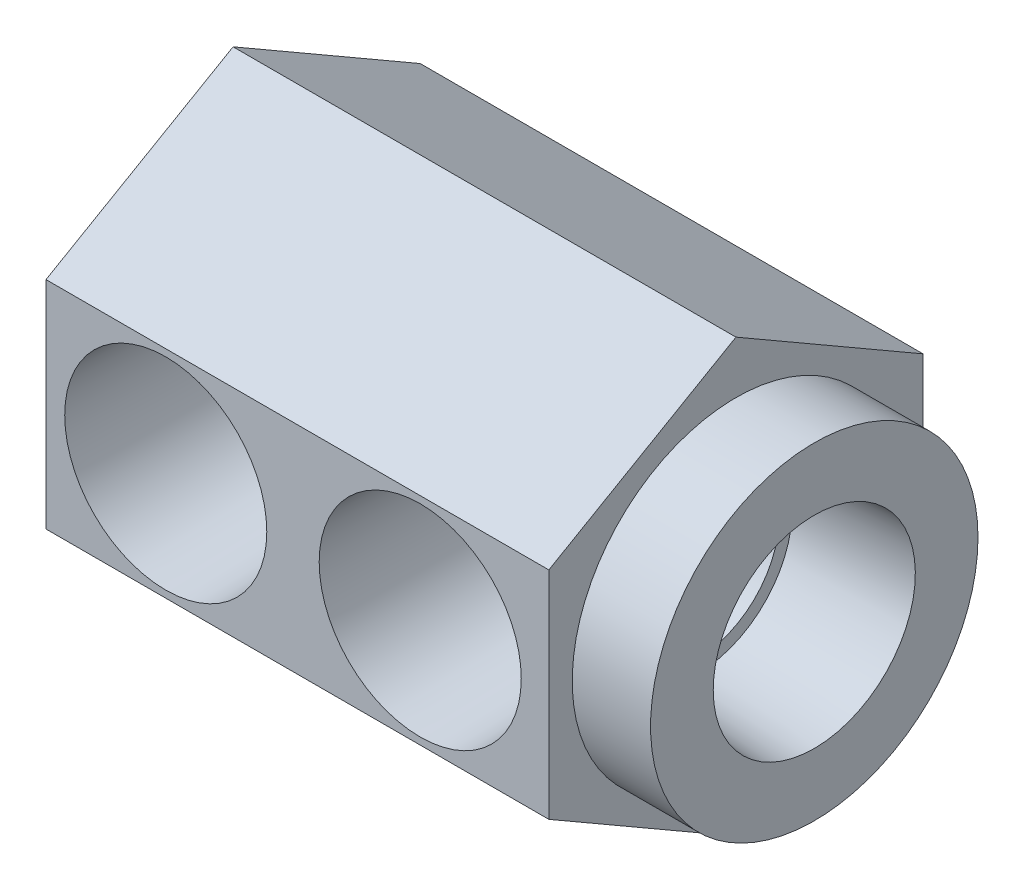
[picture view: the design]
ISO-10303-21;
HEADER;
FILE_DESCRIPTION(('STEP AP214'),'2;1');
FILE_NAME('part.step','',(''),(''),'','','');
FILE_SCHEMA(('AUTOMOTIVE_DESIGN { 1 0 10303 214 1 1 1 1 }'));
ENDSEC;
DATA;
#1=APPLICATION_CONTEXT('core data for automotive mechanical design processes');
#2=APPLICATION_PROTOCOL_DEFINITION('international standard','automotive_design',2000,#1);
#3=PRODUCT_CONTEXT('',#1,'mechanical');
#4=PRODUCT('Part','Part','',(#3));
#5=PRODUCT_RELATED_PRODUCT_CATEGORY('part','',(#4));
#6=PRODUCT_DEFINITION_FORMATION('','',#4);
#7=PRODUCT_DEFINITION_CONTEXT('part definition',#1,'design');
#8=PRODUCT_DEFINITION('design','',#6,#7);
#9=PRODUCT_DEFINITION_SHAPE('','',#8);
#10=(LENGTH_UNIT() NAMED_UNIT(*) SI_UNIT(.MILLI.,.METRE.));
#11=(NAMED_UNIT(*) PLANE_ANGLE_UNIT() SI_UNIT($,.RADIAN.));
#12=(NAMED_UNIT(*) SI_UNIT($,.STERADIAN.) SOLID_ANGLE_UNIT());
#13=UNCERTAINTY_MEASURE_WITH_UNIT(LENGTH_MEASURE(1.E-05),#10,'distance_accuracy_value','');
#14=(GEOMETRIC_REPRESENTATION_CONTEXT(3) GLOBAL_UNCERTAINTY_ASSIGNED_CONTEXT((#13)) GLOBAL_UNIT_ASSIGNED_CONTEXT((#10,
#11,#12)) REPRESENTATION_CONTEXT('',''));
#15=CARTESIAN_POINT('',(0.,0.,0.));
#16=DIRECTION('',(0.,0.,1.));
#17=DIRECTION('',(1.,0.,0.));
#18=AXIS2_PLACEMENT_3D('',#15,#16,#17);
#19=CARTESIAN_POINT('',(30.9626,0.,2.6797));
#20=DIRECTION('',(0.,0.,-1.));
#21=DIRECTION('',(-1.,0.,0.));
#22=AXIS2_PLACEMENT_3D('',#19,#20,#21);
#23=PLANE('',#22);
#24=CARTESIAN_POINT('',(25.4,0.,2.6797));
#25=DIRECTION('',(0.,0.,1.));
#26=DIRECTION('',(1.,0.,0.));
#27=AXIS2_PLACEMENT_3D('',#24,#25,#26);
#28=CIRCLE('',#27,6.55797879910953);
#29=CARTESIAN_POINT('',(29.7949930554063,4.86735266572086,2.6797));
#30=VERTEX_POINT('',#29);
#31=CARTESIAN_POINT('',(19.531703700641,2.92748774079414,2.6797));
#32=VERTEX_POINT('',#31);
#33=EDGE_CURVE('E312',#30,#32,#28,.T.);
#34=ORIENTED_EDGE('',*,*,#33,.T.);
#35=DIRECTION('',(1.,0.,0.));
#36=VECTOR('',#35,1.);
#37=CARTESIAN_POINT('',(39.44747,2.92748774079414,2.6797));
#38=LINE('',#37,#36);
#39=CARTESIAN_POINT('',(20.6700598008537,2.92748774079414,2.6797));
#40=VERTEX_POINT('',#39);
#41=EDGE_CURVE('E677',#32,#40,#38,.T.);
#42=ORIENTED_EDGE('',*,*,#41,.T.);
#43=CARTESIAN_POINT('',(25.4,0.,2.6797));
#44=DIRECTION('',(0.,0.,1.));
#45=DIRECTION('',(1.,0.,0.));
#46=AXIS2_PLACEMENT_3D('',#43,#44,#45);
#47=CIRCLE('',#46,5.56260000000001);
#48=CARTESIAN_POINT('',(28.0928417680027,4.86735266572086,2.6797));
#49=VERTEX_POINT('',#48);
#50=EDGE_CURVE('E311',#49,#40,#47,.T.);
#51=ORIENTED_EDGE('',*,*,#50,.F.);
#52=DIRECTION('',(-1.,0.,0.));
#53=VECTOR('',#52,1.);
#54=CARTESIAN_POINT('',(-12.2161702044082,4.86735266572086,2.6797));
#55=LINE('',#54,#53);
#56=EDGE_CURVE('E411',#49,#30,#55,.F.);
#57=ORIENTED_EDGE('',*,*,#56,.T.);
#58=EDGE_LOOP('',(#34,#42,#51,#57));
#59=FACE_BOUND('',#58,.T.);
#60=ADVANCED_FACE('F35',(#59),#23,.F.);
#61=CARTESIAN_POINT('',(26.74747,0.,-5.55625));
#62=DIRECTION('',(1.,0.,0.));
#63=DIRECTION('',(0.,0.,-1.));
#64=AXIS2_PLACEMENT_3D('',#61,#62,#63);
#65=PLANE('',#64);
#66=DIRECTION('',(0.,0.,1.));
#67=VECTOR('',#66,1.);
#68=CARTESIAN_POINT('',(26.74747,5.39692906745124,12.7));
#69=LINE('',#68,#67);
#70=CARTESIAN_POINT('',(26.74747,5.39692906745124,-1.32101124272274));
#71=VERTEX_POINT('',#70);
#72=CARTESIAN_POINT('',(26.74747,5.39692906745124,1.32101124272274));
#73=VERTEX_POINT('',#72);
#74=EDGE_CURVE('E324',#71,#73,#69,.T.);
#75=ORIENTED_EDGE('',*,*,#74,.F.);
#76=CARTESIAN_POINT('',(26.74747,0.,0.));
#77=DIRECTION('',(-1.,0.,0.));
#78=DIRECTION('',(0.,0.,1.));
#79=AXIS2_PLACEMENT_3D('',#76,#77,#78);
#80=CIRCLE('',#79,5.55625);
#81=EDGE_CURVE('E438',#73,#71,#80,.T.);
#82=ORIENTED_EDGE('',*,*,#81,.F.);
#83=EDGE_LOOP('',(#75,#82));
#84=FACE_BOUND('',#83,.T.);
#85=ADVANCED_FACE('F281',(#84),#65,.T.);
#86=CARTESIAN_POINT('',(39.44747,0.,0.));
#87=DIRECTION('',(1.,0.,0.));
#88=DIRECTION('',(0.,0.,-1.));
#89=AXIS2_PLACEMENT_3D('',#86,#87,#88);
#90=PLANE('',#89);
#91=CARTESIAN_POINT('',(39.44747,0.,0.));
#92=DIRECTION('',(1.,0.,0.));
#93=DIRECTION('',(0.,0.,-1.));
#94=AXIS2_PLACEMENT_3D('',#91,#92,#93);
#95=CIRCLE('',#94,11.1125);
#96=CARTESIAN_POINT('',(39.44747,0.,-11.1125));
#97=VERTEX_POINT('',#96);
#98=EDGE_CURVE('E442',#97,#97,#95,.T.);
#99=ORIENTED_EDGE('',*,*,#98,.T.);
#100=EDGE_LOOP('',(#99));
#101=FACE_BOUND('',#100,.T.);
#102=CARTESIAN_POINT('',(39.44747,0.,0.));
#103=DIRECTION('',(-1.,0.,0.));
#104=DIRECTION('',(0.,0.,1.));
#105=AXIS2_PLACEMENT_3D('',#102,#103,#104);
#106=CIRCLE('',#105,6.85927);
#107=CARTESIAN_POINT('',(39.44747,0.,6.85927));
#108=VERTEX_POINT('',#107);
#109=EDGE_CURVE('E432',#108,#108,#106,.T.);
#110=ORIENTED_EDGE('',*,*,#109,.T.);
#111=EDGE_LOOP('',(#110));
#112=FACE_BOUND('',#111,.T.);
#113=ADVANCED_FACE('F288',(#101,#112),#90,.T.);
#114=CARTESIAN_POINT('',(34.13125,-7.33234841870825,12.7));
#115=DIRECTION('',(1.,0.,0.));
#116=DIRECTION('',(0.,0.,-1.));
#117=AXIS2_PLACEMENT_3D('',#114,#115,#116);
#118=PLANE('',#117);
#119=DIRECTION('',(0.,-1.,0.));
#120=VECTOR('',#119,1.);
#121=CARTESIAN_POINT('',(34.13125,7.33234841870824,12.7));
#122=LINE('',#121,#120);
#123=CARTESIAN_POINT('',(34.13125,7.33234841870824,12.7));
#124=VERTEX_POINT('',#123);
#125=CARTESIAN_POINT('',(34.13125,-7.33234841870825,12.7));
#126=VERTEX_POINT('',#125);
#127=EDGE_CURVE('E448',#124,#126,#122,.T.);
#128=ORIENTED_EDGE('',*,*,#127,.T.);
#129=DIRECTION('',(0.,-0.5,-0.866025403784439));
#130=VECTOR('',#129,1.);
#131=CARTESIAN_POINT('',(34.13125,-7.33234841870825,12.7));
#132=LINE('',#131,#130);
#133=CARTESIAN_POINT('',(34.13125,-14.6646968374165,0.));
#134=VERTEX_POINT('',#133);
#135=EDGE_CURVE('E451',#126,#134,#132,.T.);
#136=ORIENTED_EDGE('',*,*,#135,.T.);
#137=DIRECTION('',(0.,0.500000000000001,-0.866025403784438));
#138=VECTOR('',#137,1.);
#139=CARTESIAN_POINT('',(34.13125,-14.6646968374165,0.));
#140=LINE('',#139,#138);
#141=CARTESIAN_POINT('',(34.13125,-7.33234841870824,-12.7));
#142=VERTEX_POINT('',#141);
#143=EDGE_CURVE('E454',#134,#142,#140,.T.);
#144=ORIENTED_EDGE('',*,*,#143,.T.);
#145=DIRECTION('',(0.,1.,0.));
#146=VECTOR('',#145,1.);
#147=CARTESIAN_POINT('',(34.13125,-7.33234841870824,-12.7));
#148=LINE('',#147,#146);
#149=CARTESIAN_POINT('',(34.13125,7.33234841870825,-12.7));
#150=VERTEX_POINT('',#149);
#151=EDGE_CURVE('E456',#142,#150,#148,.T.);
#152=ORIENTED_EDGE('',*,*,#151,.T.);
#153=DIRECTION('',(0.,0.5,0.866025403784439));
#154=VECTOR('',#153,1.);
#155=CARTESIAN_POINT('',(34.13125,7.33234841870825,-12.7));
#156=LINE('',#155,#154);
#157=CARTESIAN_POINT('',(34.13125,14.6646968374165,0.));
#158=VERTEX_POINT('',#157);
#159=EDGE_CURVE('E458',#150,#158,#156,.T.);
#160=ORIENTED_EDGE('',*,*,#159,.T.);
#161=DIRECTION('',(0.,-0.5,0.866025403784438));
#162=VECTOR('',#161,1.);
#163=CARTESIAN_POINT('',(34.13125,14.6646968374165,0.));
#164=LINE('',#163,#162);
#165=EDGE_CURVE('E460',#158,#124,#164,.T.);
#166=ORIENTED_EDGE('',*,*,#165,.T.);
#167=EDGE_LOOP('',(#128,#136,#144,#152,#160,#166));
#168=FACE_BOUND('',#167,.T.);
#169=CARTESIAN_POINT('',(34.13125,0.,0.));
#170=DIRECTION('',(1.,0.,0.));
#171=DIRECTION('',(0.,0.,-1.));
#172=AXIS2_PLACEMENT_3D('',#169,#170,#171);
#173=CIRCLE('',#172,11.1125);
#174=CARTESIAN_POINT('',(34.13125,0.,-11.1125));
#175=VERTEX_POINT('',#174);
#176=EDGE_CURVE('E436',#175,#175,#173,.T.);
#177=ORIENTED_EDGE('',*,*,#176,.F.);
#178=EDGE_LOOP('',(#177));
#179=FACE_BOUND('',#178,.T.);
#180=ADVANCED_FACE('F542',(#168,#179),#118,.T.);
#181=CARTESIAN_POINT('',(34.13125,7.33234841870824,12.7));
#182=DIRECTION('',(0.,0.,-1.));
#183=DIRECTION('',(0.,1.,0.));
#184=AXIS2_PLACEMENT_3D('',#181,#182,#183);
#185=PLANE('',#184);
#186=CARTESIAN_POINT('',(8.128,0.,12.7));
#187=DIRECTION('',(0.,0.,1.));
#188=DIRECTION('',(1.,0.,0.));
#189=AXIS2_PLACEMENT_3D('',#186,#187,#188);
#190=CIRCLE('',#189,6.858);
#191=CARTESIAN_POINT('',(14.986,0.,12.7));
#192=VERTEX_POINT('',#191);
#193=EDGE_CURVE('E197',#192,#192,#190,.T.);
#194=ORIENTED_EDGE('',*,*,#193,.F.);
#195=EDGE_LOOP('',(#194));
#196=FACE_BOUND('',#195,.T.);
#197=CARTESIAN_POINT('',(25.4,0.,12.7));
#198=DIRECTION('',(0.,0.,1.));
#199=DIRECTION('',(1.,0.,0.));
#200=AXIS2_PLACEMENT_3D('',#197,#198,#199);
#201=CIRCLE('',#200,6.858);
#202=CARTESIAN_POINT('',(32.258,0.,12.7));
#203=VERTEX_POINT('',#202);
#204=EDGE_CURVE('E679',#203,#203,#201,.T.);
#205=ORIENTED_EDGE('',*,*,#204,.F.);
#206=EDGE_LOOP('',(#205));
#207=FACE_BOUND('',#206,.T.);
#208=DIRECTION('',(0.,-1.,0.));
#209=VECTOR('',#208,1.);
#210=CARTESIAN_POINT('',(0.,7.33234841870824,12.7));
#211=LINE('',#210,#209);
#212=CARTESIAN_POINT('',(0.,7.33234841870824,12.7));
#213=VERTEX_POINT('',#212);
#214=CARTESIAN_POINT('',(0.,-7.33234841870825,12.7));
#215=VERTEX_POINT('',#214);
#216=EDGE_CURVE('E445',#213,#215,#211,.T.);
#217=ORIENTED_EDGE('',*,*,#216,.T.);
#218=DIRECTION('',(-1.,0.,0.));
#219=VECTOR('',#218,1.);
#220=CARTESIAN_POINT('',(34.13125,-7.33234841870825,12.7));
#221=LINE('',#220,#219);
#222=EDGE_CURVE('E487',#126,#215,#221,.T.);
#223=ORIENTED_EDGE('',*,*,#222,.F.);
#224=ORIENTED_EDGE('',*,*,#127,.F.);
#225=DIRECTION('',(-1.,0.,0.));
#226=VECTOR('',#225,1.);
#227=CARTESIAN_POINT('',(34.13125,7.33234841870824,12.7));
#228=LINE('',#227,#226);
#229=EDGE_CURVE('E462',#124,#213,#228,.T.);
#230=ORIENTED_EDGE('',*,*,#229,.T.);
#231=EDGE_LOOP('',(#217,#223,#224,#230));
#232=FACE_BOUND('',#231,.T.);
#233=ADVANCED_FACE('F37',(#196,#207,#232),#185,.F.);
#234=CARTESIAN_POINT('',(34.13125,-7.33234841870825,12.7));
#235=DIRECTION('',(0.,0.866025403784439,-0.5));
#236=DIRECTION('',(0.,0.5,0.866025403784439));
#237=AXIS2_PLACEMENT_3D('',#234,#235,#236);
#238=PLANE('',#237);
#239=DIRECTION('',(0.,-0.5,-0.866025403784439));
#240=VECTOR('',#239,1.);
#241=CARTESIAN_POINT('',(0.,-7.33234841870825,12.7));
#242=LINE('',#241,#240);
#243=CARTESIAN_POINT('',(0.,-14.6646968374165,0.));
#244=VERTEX_POINT('',#243);
#245=EDGE_CURVE('E465',#215,#244,#242,.T.);
#246=ORIENTED_EDGE('',*,*,#245,.T.);
#247=DIRECTION('',(-1.,0.,0.));
#248=VECTOR('',#247,1.);
#249=CARTESIAN_POINT('',(34.13125,-14.6646968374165,0.));
#250=LINE('',#249,#248);
#251=EDGE_CURVE('E485',#134,#244,#250,.T.);
#252=ORIENTED_EDGE('',*,*,#251,.F.);
#253=ORIENTED_EDGE('',*,*,#135,.F.);
#254=ORIENTED_EDGE('',*,*,#222,.T.);
#255=EDGE_LOOP('',(#246,#252,#253,#254));
#256=FACE_BOUND('',#255,.T.);
#257=ADVANCED_FACE('F547',(#256),#238,.F.);
#258=CARTESIAN_POINT('',(34.13125,-14.6646968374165,0.));
#259=DIRECTION('',(0.,0.866025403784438,0.500000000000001));
#260=DIRECTION('',(0.,-0.500000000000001,0.866025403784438));
#261=AXIS2_PLACEMENT_3D('',#258,#259,#260);
#262=PLANE('',#261);
#263=DIRECTION('',(0.,0.500000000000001,-0.866025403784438));
#264=VECTOR('',#263,1.);
#265=CARTESIAN_POINT('',(0.,-14.6646968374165,0.));
#266=LINE('',#265,#264);
#267=CARTESIAN_POINT('',(0.,-7.33234841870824,-12.7));
#268=VERTEX_POINT('',#267);
#269=EDGE_CURVE('E467',#244,#268,#266,.T.);
#270=ORIENTED_EDGE('',*,*,#269,.T.);
#271=DIRECTION('',(-1.,0.,0.));
#272=VECTOR('',#271,1.);
#273=CARTESIAN_POINT('',(34.13125,-7.33234841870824,-12.7));
#274=LINE('',#273,#272);
#275=EDGE_CURVE('E482',#142,#268,#274,.T.);
#276=ORIENTED_EDGE('',*,*,#275,.F.);
#277=ORIENTED_EDGE('',*,*,#143,.F.);
#278=ORIENTED_EDGE('',*,*,#251,.T.);
#279=EDGE_LOOP('',(#270,#276,#277,#278));
#280=FACE_BOUND('',#279,.T.);
#281=ADVANCED_FACE('F520',(#280),#262,.F.);
#282=CARTESIAN_POINT('',(34.13125,-7.33234841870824,-12.7));
#283=DIRECTION('',(0.,0.,1.));
#284=DIRECTION('',(0.,-1.,0.));
#285=AXIS2_PLACEMENT_3D('',#282,#283,#284);
#286=PLANE('',#285);
#287=CARTESIAN_POINT('',(8.128,0.,-12.7));
#288=DIRECTION('',(0.,0.,-1.));
#289=DIRECTION('',(0.,1.,0.));
#290=AXIS2_PLACEMENT_3D('',#287,#288,#289);
#291=CIRCLE('',#290,6.858);
#292=CARTESIAN_POINT('',(8.128,6.858,-12.7));
#293=VERTEX_POINT('',#292);
#294=EDGE_CURVE('E332',#293,#293,#291,.T.);
#295=ORIENTED_EDGE('',*,*,#294,.F.);
#296=EDGE_LOOP('',(#295));
#297=FACE_BOUND('',#296,.T.);
#298=DIRECTION('',(0.,1.,0.));
#299=VECTOR('',#298,1.);
#300=CARTESIAN_POINT('',(0.,-7.33234841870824,-12.7));
#301=LINE('',#300,#299);
#302=CARTESIAN_POINT('',(0.,7.33234841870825,-12.7));
#303=VERTEX_POINT('',#302);
#304=EDGE_CURVE('E469',#268,#303,#301,.T.);
#305=ORIENTED_EDGE('',*,*,#304,.T.);
#306=DIRECTION('',(-1.,0.,0.));
#307=VECTOR('',#306,1.);
#308=CARTESIAN_POINT('',(34.13125,7.33234841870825,-12.7));
#309=LINE('',#308,#307);
#310=EDGE_CURVE('E479',#150,#303,#309,.T.);
#311=ORIENTED_EDGE('',*,*,#310,.F.);
#312=ORIENTED_EDGE('',*,*,#151,.F.);
#313=ORIENTED_EDGE('',*,*,#275,.T.);
#314=EDGE_LOOP('',(#305,#311,#312,#313));
#315=FACE_BOUND('',#314,.T.);
#316=ADVANCED_FACE('F516',(#297,#315),#286,.F.);
#317=CARTESIAN_POINT('',(34.13125,7.33234841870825,-12.7));
#318=DIRECTION('',(0.,-0.866025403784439,0.5));
#319=DIRECTION('',(0.,-0.5,-0.866025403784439));
#320=AXIS2_PLACEMENT_3D('',#317,#318,#319);
#321=PLANE('',#320);
#322=DIRECTION('',(0.,0.5,0.866025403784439));
#323=VECTOR('',#322,1.);
#324=CARTESIAN_POINT('',(0.,7.33234841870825,-12.7));
#325=LINE('',#324,#323);
#326=CARTESIAN_POINT('',(0.,14.6646968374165,0.));
#327=VERTEX_POINT('',#326);
#328=EDGE_CURVE('E471',#303,#327,#325,.T.);
#329=ORIENTED_EDGE('',*,*,#328,.T.);
#330=DIRECTION('',(-1.,0.,0.));
#331=VECTOR('',#330,1.);
#332=CARTESIAN_POINT('',(34.13125,14.6646968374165,0.));
#333=LINE('',#332,#331);
#334=EDGE_CURVE('E476',#158,#327,#333,.T.);
#335=ORIENTED_EDGE('',*,*,#334,.F.);
#336=ORIENTED_EDGE('',*,*,#159,.F.);
#337=ORIENTED_EDGE('',*,*,#310,.T.);
#338=EDGE_LOOP('',(#329,#335,#336,#337));
#339=FACE_BOUND('',#338,.T.);
#340=ADVANCED_FACE('F519',(#339),#321,.F.);
#341=CARTESIAN_POINT('',(34.13125,14.6646968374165,0.));
#342=DIRECTION('',(0.,-0.866025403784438,-0.5));
#343=DIRECTION('',(0.,0.5,-0.866025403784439));
#344=AXIS2_PLACEMENT_3D('',#341,#342,#343);
#345=PLANE('',#344);
#346=DIRECTION('',(0.,-0.5,0.866025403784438));
#347=VECTOR('',#346,1.);
#348=CARTESIAN_POINT('',(0.,14.6646968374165,0.));
#349=LINE('',#348,#347);
#350=EDGE_CURVE('E452',#327,#213,#349,.T.);
#351=ORIENTED_EDGE('',*,*,#350,.T.);
#352=ORIENTED_EDGE('',*,*,#229,.F.);
#353=ORIENTED_EDGE('',*,*,#165,.F.);
#354=ORIENTED_EDGE('',*,*,#334,.T.);
#355=EDGE_LOOP('',(#351,#352,#353,#354));
#356=FACE_BOUND('',#355,.T.);
#357=ADVANCED_FACE('F537',(#356),#345,.F.);
#358=CARTESIAN_POINT('',(0.,-7.33234841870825,12.7));
#359=DIRECTION('',(1.,0.,0.));
#360=DIRECTION('',(0.,0.,-1.));
#361=AXIS2_PLACEMENT_3D('',#358,#359,#360);
#362=PLANE('',#361);
#363=ORIENTED_EDGE('',*,*,#216,.F.);
#364=ORIENTED_EDGE('',*,*,#350,.F.);
#365=ORIENTED_EDGE('',*,*,#328,.F.);
#366=ORIENTED_EDGE('',*,*,#304,.F.);
#367=ORIENTED_EDGE('',*,*,#269,.F.);
#368=ORIENTED_EDGE('',*,*,#245,.F.);
#369=EDGE_LOOP('',(#363,#364,#365,#366,#367,#368));
#370=FACE_BOUND('',#369,.T.);
#371=ADVANCED_FACE('F534',(#370),#362,.F.);
#372=CARTESIAN_POINT('',(39.44747,0.,0.));
#373=DIRECTION('',(-1.,0.,0.));
#374=DIRECTION('',(0.,0.,1.));
#375=AXIS2_PLACEMENT_3D('',#372,#373,#374);
#376=CYLINDRICAL_SURFACE('',#375,11.1125);
#377=ORIENTED_EDGE('',*,*,#98,.F.);
#378=EDGE_LOOP('',(#377));
#379=FACE_BOUND('',#378,.T.);
#380=ORIENTED_EDGE('',*,*,#176,.T.);
#381=EDGE_LOOP('',(#380));
#382=FACE_BOUND('',#381,.T.);
#383=ADVANCED_FACE('F562',(#379,#382),#376,.T.);
#384=CARTESIAN_POINT('',(39.44747,0.,0.));
#385=DIRECTION('',(1.,0.,0.));
#386=DIRECTION('',(0.,0.,-1.));
#387=AXIS2_PLACEMENT_3D('',#384,#385,#386);
#388=CONICAL_SURFACE('',#387,6.85927,0.0523598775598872);
#389=CARTESIAN_POINT('',(31.434967,2.79651950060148,5.80040855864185));
#390=CARTESIAN_POINT('',(31.4885738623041,2.68491125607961,5.85734580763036));
#391=CARTESIAN_POINT('',(31.5395481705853,2.57051306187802,5.9113986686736));
#392=CARTESIAN_POINT('',(31.6356400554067,2.33643131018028,6.01316652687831));
#393=CARTESIAN_POINT('',(31.6807526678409,2.21674338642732,6.06087615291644));
#394=CARTESIAN_POINT('',(31.7646308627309,1.97200075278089,6.14949518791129));
#395=CARTESIAN_POINT('',(31.8033661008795,1.84692376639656,6.19037209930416));
#396=CARTESIAN_POINT('',(31.8736020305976,1.59255780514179,6.2644343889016));
#397=CARTESIAN_POINT('',(31.9051046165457,1.46326994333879,6.29762178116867));
#398=CARTESIAN_POINT('',(31.9604703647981,1.20051379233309,6.35591633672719));
#399=CARTESIAN_POINT('',(31.9842919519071,1.06702690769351,6.380979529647));
#400=CARTESIAN_POINT('',(32.0235910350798,0.797488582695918,6.42231247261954));
#401=CARTESIAN_POINT('',(32.0390691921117,0.661437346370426,6.43858291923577));
#402=CARTESIAN_POINT('',(32.0613239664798,0.388244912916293,6.46197333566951));
#403=CARTESIAN_POINT('',(32.0681260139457,0.25110809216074,6.46912004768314));
#404=CARTESIAN_POINT('',(32.0729626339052,-0.0234825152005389,6.47420197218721));
#405=CARTESIAN_POINT('',(32.0709980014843,-0.160936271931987,6.47213802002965));
#406=CARTESIAN_POINT('',(32.058806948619,-0.425053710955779,6.45932755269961));
#407=CARTESIAN_POINT('',(32.0491894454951,-0.551777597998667,6.44922096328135));
#408=CARTESIAN_POINT('',(32.0226279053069,-0.80364039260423,6.42129811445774));
#409=CARTESIAN_POINT('',(32.005681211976,-0.928778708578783,6.40347905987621));
#410=CARTESIAN_POINT('',(31.964723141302,-1.17682126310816,6.36038910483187));
#411=CARTESIAN_POINT('',(31.9406993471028,-1.29972116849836,6.33510510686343));
#412=CARTESIAN_POINT('',(31.8860008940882,-1.54235323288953,6.27749566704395));
#413=CARTESIAN_POINT('',(31.8553245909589,-1.66208460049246,6.24516848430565));
#414=CARTESIAN_POINT('',(31.7700806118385,-1.95951809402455,6.15525600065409));
#415=CARTESIAN_POINT('',(31.7114113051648,-2.13476678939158,6.09330594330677));
#416=CARTESIAN_POINT('',(31.6141871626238,-2.38938982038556,5.9904492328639));
#417=CARTESIAN_POINT('',(31.5803287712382,-2.47271111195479,5.95460001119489));
#418=CARTESIAN_POINT('',(31.5097463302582,-2.63664903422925,5.87978975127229));
#419=CARTESIAN_POINT('',(31.4730236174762,-2.71726690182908,5.84083016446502));
#420=CARTESIAN_POINT('',(31.434967,-2.79651950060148,5.80040855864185));
#421=B_SPLINE_CURVE_WITH_KNOTS('',3,(#389,#390,#391,#392,#393,#394,#395,#396,#397,#398,#399,
#400,#401,#402,#403,#404,#405,#406,#407,#408,#409,#410,#411,#412,#413,#414,#415,#416,#417,#418,
#419,#420),.UNSPECIFIED.,.F.,.F.,(4,2,2,2,2,2,2,2,2,2,2,2,2,2,2,4),(0.,0.408818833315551,
0.817981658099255,1.22903833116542,1.6399872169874,2.05312450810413,2.46622906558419,
2.87811998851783,3.28997355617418,3.6719864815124,4.05413797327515,4.43696398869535,
4.81988473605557,5.4031989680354,5.69355402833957,5.98377437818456),.UNSPECIFIED.);
#422=CARTESIAN_POINT('',(31.50997,2.63463996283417,5.88001456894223));
#423=VERTEX_POINT('',#422);
#424=CARTESIAN_POINT('',(31.50997,-2.63463996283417,5.88001456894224));
#425=VERTEX_POINT('',#424);
#426=EDGE_CURVE('E326',#423,#425,#421,.T.);
#427=ORIENTED_EDGE('',*,*,#426,.F.);
#428=CARTESIAN_POINT('',(31.50997,0.,0.));
#429=DIRECTION('',(-1.,0.,0.));
#430=DIRECTION('',(0.,0.,1.));
#431=AXIS2_PLACEMENT_3D('',#428,#429,#430);
#432=CIRCLE('',#431,6.4432832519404);
#433=EDGE_CURVE('E431',#423,#425,#432,.T.);
#434=ORIENTED_EDGE('',*,*,#433,.T.);
#435=EDGE_LOOP('',(#427,#434));
#436=FACE_BOUND('',#435,.T.);
#437=ORIENTED_EDGE('',*,*,#109,.F.);
#438=EDGE_LOOP('',(#437));
#439=FACE_BOUND('',#438,.T.);
#440=ADVANCED_FACE('F334',(#436,#439),#388,.F.);
#441=CARTESIAN_POINT('',(31.50997,0.,-5.55625));
#442=DIRECTION('',(1.,0.,0.));
#443=DIRECTION('',(0.,0.,-1.));
#444=AXIS2_PLACEMENT_3D('',#441,#442,#443);
#445=PLANE('',#444);
#446=CARTESIAN_POINT('',(31.50997,-3.40485172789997,17.2630170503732));
#447=CARTESIAN_POINT('',(31.50997,-3.33912103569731,16.1949703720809));
#448=CARTESIAN_POINT('',(31.50997,-3.27201398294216,15.127006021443));
#449=CARTESIAN_POINT('',(31.50997,-3.13431515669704,12.991328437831));
#450=CARTESIAN_POINT('',(31.50997,-3.06372346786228,11.923615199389));
#451=CARTESIAN_POINT('',(31.50997,-2.91834199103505,9.78879369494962));
#452=CARTESIAN_POINT('',(31.50997,-2.84355346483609,8.72168534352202));
#453=CARTESIAN_POINT('',(31.50997,-2.68864021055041,6.58782277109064));
#454=CARTESIAN_POINT('',(31.50997,-2.60851532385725,5.52106856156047));
#455=CARTESIAN_POINT('',(31.50997,-2.44128073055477,3.3876946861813));
#456=CARTESIAN_POINT('',(31.50997,-2.35416839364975,2.32107522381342));
#457=CARTESIAN_POINT('',(31.50997,-2.21624588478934,0.721810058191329));
#458=CARTESIAN_POINT('',(31.50997,-2.16906454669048,0.188851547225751));
#459=CARTESIAN_POINT('',(31.50997,-2.07174805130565,-0.87680396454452));
#460=CARTESIAN_POINT('',(31.50997,-2.02161285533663,-1.40950096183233));
#461=CARTESIAN_POINT('',(31.50997,-1.91766350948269,-2.47471868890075));
#462=CARTESIAN_POINT('',(31.50997,-1.863848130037,-3.00723929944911));
#463=CARTESIAN_POINT('',(31.50997,-1.75150147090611,-4.07176620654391));
#464=CARTESIAN_POINT('',(31.50997,-1.69297035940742,-4.60377252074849));
#465=CARTESIAN_POINT('',(31.50997,-1.569551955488,-5.66718749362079));
#466=CARTESIAN_POINT('',(31.50997,-1.50466316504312,-6.19859598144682));
#467=CARTESIAN_POINT('',(31.50997,-1.40040042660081,-6.99483769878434));
#468=CARTESIAN_POINT('',(31.50997,-1.36448891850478,-7.26012215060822));
#469=CARTESIAN_POINT('',(31.50997,-1.28967950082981,-7.79027968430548));
#470=CARTESIAN_POINT('',(31.50997,-1.25078146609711,-8.05515274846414));
#471=CARTESIAN_POINT('',(31.50997,-1.21005294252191,-8.31975375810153));
#472=B_SPLINE_CURVE_WITH_KNOTS('',3,(#446,#447,#448,#449,#450,#451,#452,#453,#454,#455,#456,
#457,#458,#459,#460,#461,#462,#463,#464,#465,#466,#467,#468,#469,#470,#471),.UNSPECIFIED.,.F.,
.F.,(4,2,2,2,2,2,2,2,2,2,2,2,4),(0.,3.21020479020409,6.42033163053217,9.62949845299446,
12.8387607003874,16.0492367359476,17.654358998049,19.2595022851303,20.8651845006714,
22.470809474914,24.0768136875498,24.8799111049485,25.6830421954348),.UNSPECIFIED.);
#473=CARTESIAN_POINT('',(31.50997,-2.56197927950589,4.93033226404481));
#474=VERTEX_POINT('',#473);
#475=EDGE_CURVE('E365',#425,#474,#472,.T.);
#476=ORIENTED_EDGE('',*,*,#475,.F.);
#477=ORIENTED_EDGE('',*,*,#433,.F.);
#478=CARTESIAN_POINT('',(31.50997,1.21005294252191,-8.31975375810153));
#479=CARTESIAN_POINT('',(31.50997,1.25078146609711,-8.05515274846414));
#480=CARTESIAN_POINT('',(31.50997,1.28967950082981,-7.79027968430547));
#481=CARTESIAN_POINT('',(31.50997,1.36448891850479,-7.26012215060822));
#482=CARTESIAN_POINT('',(31.50997,1.40040042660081,-6.99483769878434));
#483=CARTESIAN_POINT('',(31.50997,1.50466316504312,-6.19859598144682));
#484=CARTESIAN_POINT('',(31.50997,1.569551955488,-5.6671874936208));
#485=CARTESIAN_POINT('',(31.50997,1.69297035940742,-4.60377252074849));
#486=CARTESIAN_POINT('',(31.50997,1.75150147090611,-4.07176620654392));
#487=CARTESIAN_POINT('',(31.50997,1.863848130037,-3.00723929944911));
#488=CARTESIAN_POINT('',(31.50997,1.91766350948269,-2.47471868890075));
#489=CARTESIAN_POINT('',(31.50997,2.02161285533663,-1.40950096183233));
#490=CARTESIAN_POINT('',(31.50997,2.07174805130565,-0.87680396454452));
#491=CARTESIAN_POINT('',(31.50997,2.16906454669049,0.188851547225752));
#492=CARTESIAN_POINT('',(31.50997,2.21624588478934,0.721810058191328));
#493=CARTESIAN_POINT('',(31.50997,2.35416839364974,2.32107522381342));
#494=CARTESIAN_POINT('',(31.50997,2.44128073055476,3.3876946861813));
#495=CARTESIAN_POINT('',(31.50997,2.60851532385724,5.52106856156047));
#496=CARTESIAN_POINT('',(31.50997,2.6886402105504,6.58782277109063));
#497=CARTESIAN_POINT('',(31.50997,2.8435534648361,8.72168534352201));
#498=CARTESIAN_POINT('',(31.50997,2.91834199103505,9.78879369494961));
#499=CARTESIAN_POINT('',(31.50997,3.06372346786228,11.923615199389));
#500=CARTESIAN_POINT('',(31.50997,3.13431515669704,12.991328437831));
#501=CARTESIAN_POINT('',(31.50997,3.27201398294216,15.127006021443));
#502=CARTESIAN_POINT('',(31.50997,3.33912103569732,16.1949703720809));
#503=CARTESIAN_POINT('',(31.50997,3.40485172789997,17.2630170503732));
#504=B_SPLINE_CURVE_WITH_KNOTS('',3,(#478,#479,#480,#481,#482,#483,#484,#485,#486,#487,#488,
#489,#490,#491,#492,#493,#494,#495,#496,#497,#498,#499,#500,#501,#502,#503),.UNSPECIFIED.,.F.,
.F.,(4,2,2,2,2,2,2,2,2,2,2,2,4),(0.,0.80313109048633,1.606228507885,3.21223272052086,
4.81785769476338,6.42353991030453,8.02868319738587,9.63380545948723,12.8442814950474,
16.0535437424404,19.2627105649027,22.4728374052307,25.6830421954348),.UNSPECIFIED.);
#505=CARTESIAN_POINT('',(31.50997,2.5619792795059,4.93033226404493));
#506=VERTEX_POINT('',#505);
#507=EDGE_CURVE('E360',#506,#423,#504,.T.);
#508=ORIENTED_EDGE('',*,*,#507,.F.);
#509=CARTESIAN_POINT('',(31.50997,0.,0.));
#510=DIRECTION('',(-1.,0.,0.));
#511=DIRECTION('',(0.,0.,1.));
#512=AXIS2_PLACEMENT_3D('',#509,#510,#511);
#513=CIRCLE('',#512,5.55625);
#514=EDGE_CURVE('E433',#506,#474,#513,.T.);
#515=ORIENTED_EDGE('',*,*,#514,.T.);
#516=EDGE_LOOP('',(#476,#477,#508,#515));
#517=FACE_BOUND('',#516,.T.);
#518=ADVANCED_FACE('F371',(#517),#445,.T.);
#519=CARTESIAN_POINT('',(-12.2161702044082,0.,0.));
#520=DIRECTION('',(-1.,0.,0.));
#521=DIRECTION('',(0.,0.,1.));
#522=AXIS2_PLACEMENT_3D('',#519,#520,#521);
#523=CYLINDRICAL_SURFACE('',#522,5.55625);
#524=CARTESIAN_POINT('',(29.7948621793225,4.86746276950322,2.6795));
#525=CARTESIAN_POINT('',(29.8445921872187,4.82562929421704,2.75548249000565));
#526=CARTESIAN_POINT('',(29.8946694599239,4.78212945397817,2.83030157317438));
#527=CARTESIAN_POINT('',(29.9951871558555,4.6917996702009,2.97765187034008));
#528=CARTESIAN_POINT('',(30.045627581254,4.64496970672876,3.05018307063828));
#529=CARTESIAN_POINT('',(30.1970973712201,4.49939154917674,3.26454593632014));
#530=CARTESIAN_POINT('',(30.2981736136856,4.39563946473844,3.40299377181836));
#531=CARTESIAN_POINT('',(30.4956476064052,4.17747567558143,3.66732242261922));
#532=CARTESIAN_POINT('',(30.5920993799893,4.06338283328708,3.79342633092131));
#533=CARTESIAN_POINT('',(30.7808405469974,3.82247833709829,4.03605959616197));
#534=CARTESIAN_POINT('',(30.8731327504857,3.6956754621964,4.152595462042));
#535=CARTESIAN_POINT('',(31.0626619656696,3.41285072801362,4.38888939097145));
#536=CARTESIAN_POINT('',(31.1591177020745,3.25515259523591,4.50729046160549));
#537=CARTESIAN_POINT('',(31.3428274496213,2.92161129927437,4.73041758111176));
#538=CARTESIAN_POINT('',(31.4299369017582,2.74554869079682,4.83493350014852));
#539=CARTESIAN_POINT('',(31.51017,2.56152070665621,4.93057052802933));
#540=B_SPLINE_CURVE_WITH_KNOTS('',3,(#524,#525,#526,#527,#528,#529,#530,#531,#532,#533,#534,
#535,#536,#537,#538,#539),.UNSPECIFIED.,.F.,.F.,(4,2,2,2,2,2,2,4),(0.,0.299898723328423,
0.599799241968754,1.20020513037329,1.78607590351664,2.37154476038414,3.02880159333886,
3.6950845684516),.UNSPECIFIED.);
#541=EDGE_CURVE('E353',#30,#506,#540,.T.);
#542=ORIENTED_EDGE('',*,*,#541,.F.);
#543=ORIENTED_EDGE('',*,*,#56,.F.);
#544=CARTESIAN_POINT('',(26.74747,5.39692906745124,1.32101124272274));
#545=CARTESIAN_POINT('',(26.8618397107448,5.36837530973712,1.4376105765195));
#546=CARTESIAN_POINT('',(26.9759833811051,5.33601334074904,1.55351390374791));
#547=CARTESIAN_POINT('',(27.2030752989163,5.26361106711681,1.78349352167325));
#548=CARTESIAN_POINT('',(27.3160257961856,5.22358984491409,1.89757360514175));
#549=CARTESIAN_POINT('',(27.5405600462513,5.135666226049,2.12405167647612));
#550=CARTESIAN_POINT('',(27.6521437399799,5.08776349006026,2.23644959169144));
#551=CARTESIAN_POINT('',(27.8738024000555,4.98375616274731,2.45952188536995));
#552=CARTESIAN_POINT('',(27.9838729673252,4.92763163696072,2.5701913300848));
#553=CARTESIAN_POINT('',(28.0928417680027,4.86735266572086,2.6797));
#554=B_SPLINE_CURVE_WITH_KNOTS('',3,(#544,#545,#546,#547,#548,#549,#550,#551,#552,#553),
.UNSPECIFIED.,.F.,.F.,(4,2,2,2,4),(0.,0.497383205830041,0.993542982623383,1.48972412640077,
1.98712885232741),.UNSPECIFIED.);
#555=EDGE_CURVE('E407',#73,#49,#554,.T.);
#556=ORIENTED_EDGE('',*,*,#555,.F.);
#557=ORIENTED_EDGE('',*,*,#81,.T.);
#558=CARTESIAN_POINT('',(29.7768731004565,3.43300169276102,-4.3688));
#559=CARTESIAN_POINT('',(29.7138169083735,3.51338859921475,-4.30562720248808));
#560=CARTESIAN_POINT('',(29.6491840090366,3.59123736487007,-4.24086990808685));
#561=CARTESIAN_POINT('',(29.517108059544,3.74192239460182,-4.10852672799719));
#562=CARTESIAN_POINT('',(29.4496660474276,3.81476048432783,-4.04094188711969));
#563=CARTESIAN_POINT('',(29.2438447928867,4.02565791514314,-3.83466068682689));
#564=CARTESIAN_POINT('',(29.1017153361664,4.15642143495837,-3.69218220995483));
#565=CARTESIAN_POINT('',(28.8128573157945,4.39652814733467,-3.40251476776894));
#566=CARTESIAN_POINT('',(28.6662889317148,4.50626488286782,-3.25548848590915));
#567=CARTESIAN_POINT('',(28.3673919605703,4.70846775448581,-2.95549844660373));
#568=CARTESIAN_POINT('',(28.2150615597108,4.80092839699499,-2.80253281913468));
#569=CARTESIAN_POINT('',(27.8494067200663,5.00007149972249,-2.43504787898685));
#570=CARTESIAN_POINT('',(27.6341709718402,5.09956614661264,-2.21849750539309));
#571=CARTESIAN_POINT('',(27.3059895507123,5.22721425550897,-1.88743647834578));
#572=CARTESIAN_POINT('',(27.1948688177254,5.26637116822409,-1.77519287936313));
#573=CARTESIAN_POINT('',(26.9717354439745,5.33721552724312,-1.54920262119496));
#574=CARTESIAN_POINT('',(26.859722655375,5.36890170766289,-1.43545571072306));
#575=CARTESIAN_POINT('',(26.74747,5.39692906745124,-1.32101124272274));
#576=B_SPLINE_CURVE_WITH_KNOTS('',3,(#558,#559,#560,#561,#562,#563,#564,#565,#566,#567,#568,
#569,#570,#571,#572,#573,#574,#575),.UNSPECIFIED.,.F.,.F.,(4,2,2,2,2,2,2,2,4),(0.,
0.360250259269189,0.720368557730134,1.43916304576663,2.14280040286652,2.8466611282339,
3.80823150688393,4.29626330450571,4.78437773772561),.UNSPECIFIED.);
#577=CARTESIAN_POINT('',(29.7768731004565,3.43300169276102,-4.3688));
#578=VERTEX_POINT('',#577);
#579=EDGE_CURVE('E391',#578,#71,#576,.T.);
#580=ORIENTED_EDGE('',*,*,#579,.F.);
#581=CARTESIAN_POINT('',(29.9136879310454,-3.57919635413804,-4.24985499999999));
#582=CARTESIAN_POINT('',(29.8518661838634,-3.51715073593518,-4.30210630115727));
#583=CARTESIAN_POINT('',(29.7924236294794,-3.45251308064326,-4.3542235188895));
#584=CARTESIAN_POINT('',(29.679086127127,-3.31781322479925,-4.45771939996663));
#585=CARTESIAN_POINT('',(29.6251986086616,-3.24774397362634,-4.50909699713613));
#586=CARTESIAN_POINT('',(29.5244326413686,-3.10282888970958,-4.60999733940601));
#587=CARTESIAN_POINT('',(29.4774897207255,-3.02803759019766,-4.659533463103));
#588=CARTESIAN_POINT('',(29.3906820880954,-2.87325035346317,-4.75654092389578));
#589=CARTESIAN_POINT('',(29.3508135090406,-2.79325729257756,-4.80401337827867));
#590=CARTESIAN_POINT('',(29.2781921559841,-2.62782789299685,-4.89647589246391));
#591=CARTESIAN_POINT('',(29.2454948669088,-2.54235529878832,-4.94144471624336));
#592=CARTESIAN_POINT('',(29.1874503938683,-2.36716350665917,-5.02772181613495));
#593=CARTESIAN_POINT('',(29.1621046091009,-2.27744350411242,-5.06902939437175));
#594=CARTESIAN_POINT('',(29.1180933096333,-2.09443180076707,-5.14734778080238));
#595=CARTESIAN_POINT('',(29.0994364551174,-2.00113564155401,-5.18435297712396));
#596=CARTESIAN_POINT('',(29.0678152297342,-1.81181007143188,-5.25351563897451));
#597=CARTESIAN_POINT('',(29.0548529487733,-1.7157796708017,-5.28567132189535));
#598=CARTESIAN_POINT('',(29.0291341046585,-1.48286534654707,-5.35660102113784));
#599=CARTESIAN_POINT('',(29.0185280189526,-1.34498525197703,-5.392887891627));
#600=CARTESIAN_POINT('',(29.0028926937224,-1.06653212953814,-5.45479574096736));
#601=CARTESIAN_POINT('',(28.997865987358,-0.925957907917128,-5.48041187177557));
#602=CARTESIAN_POINT('',(28.9908710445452,-0.64276420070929,-5.52080475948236));
#603=CARTESIAN_POINT('',(28.9889120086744,-0.500139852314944,-5.53554883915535));
#604=CARTESIAN_POINT('',(28.9865721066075,-0.214200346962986,-5.5539675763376));
#605=CARTESIAN_POINT('',(28.9861909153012,-0.0708853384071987,-5.55764451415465));
#606=CARTESIAN_POINT('',(28.986626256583,0.219543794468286,-5.5538617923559));
#607=CARTESIAN_POINT('',(28.9874760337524,0.366653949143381,-5.5460929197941));
#608=CARTESIAN_POINT('',(28.9912809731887,0.659817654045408,-5.51889746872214));
#609=CARTESIAN_POINT('',(28.9942367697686,0.805870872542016,-5.4994673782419));
#610=CARTESIAN_POINT('',(29.0043155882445,1.0953130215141,-5.4491926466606));
#611=CARTESIAN_POINT('',(29.0114231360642,1.2387098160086,-5.41839054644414));
#612=CARTESIAN_POINT('',(29.0328902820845,1.5220930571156,-5.34569900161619));
#613=CARTESIAN_POINT('',(29.0472450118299,1.66208172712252,-5.30381700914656));
#614=CARTESIAN_POINT('',(29.0804482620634,1.8928132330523,-5.22483620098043));
#615=CARTESIAN_POINT('',(29.0963730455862,1.98493317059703,-5.1905209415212));
#616=CARTESIAN_POINT('',(29.1342603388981,2.16614777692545,-5.117543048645));
#617=CARTESIAN_POINT('',(29.1562206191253,2.25524354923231,-5.07888202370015));
#618=CARTESIAN_POINT('',(29.2069392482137,2.42967455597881,-4.99778402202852));
#619=CARTESIAN_POINT('',(29.2356951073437,2.51501115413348,-4.95534843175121));
#620=CARTESIAN_POINT('',(29.3003522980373,2.68126823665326,-4.86739745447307));
#621=CARTESIAN_POINT('',(29.3362526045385,2.76218935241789,-4.8218825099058));
#622=CARTESIAN_POINT('',(29.4105049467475,2.91002773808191,-4.73393872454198));
#623=CARTESIAN_POINT('',(29.4480924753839,2.97748188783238,-4.69176228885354));
#624=CARTESIAN_POINT('',(29.5284205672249,3.10838312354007,-4.60608172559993));
#625=CARTESIAN_POINT('',(29.5711624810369,3.17182915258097,-4.56257725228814));
#626=CARTESIAN_POINT('',(29.6615117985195,3.29494804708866,-4.47448250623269));
#627=CARTESIAN_POINT('',(29.7091413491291,3.35460155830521,-4.42988805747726));
#628=CARTESIAN_POINT('',(29.8084860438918,3.4698754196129,-4.34018436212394));
#629=CARTESIAN_POINT('',(29.8601975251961,3.52549930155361,-4.29507560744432));
#630=CARTESIAN_POINT('',(29.9136879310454,3.57919635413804,-4.24985499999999));
#631=B_SPLINE_CURVE_WITH_KNOTS('',3,(#581,#582,#583,#584,#585,#586,#587,#588,#589,#590,#591,
#592,#593,#594,#595,#596,#597,#598,#599,#600,#601,#602,#603,#604,#605,#606,#607,#608,#609,#610,
#611,#612,#613,#614,#615,#616,#617,#618,#619,#620,#621,#622,#623,#624,#625,#626,#627,#628,#629,
#630),.UNSPECIFIED.,.F.,.F.,(4,2,2,2,2,2,2,2,2,2,2,2,2,2,2,2,2,2,2,2,2,2,2,2,4),(0.,
0.306006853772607,0.612417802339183,0.915776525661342,1.2189689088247,1.52443027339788,
1.82994973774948,2.13586334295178,2.44188912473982,2.87015800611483,3.29862125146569,
3.72836710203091,4.15802440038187,4.59950393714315,5.04111649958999,5.4810935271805,
5.9207753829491,6.21925188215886,6.51761826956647,6.81587551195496,7.11408999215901,
7.37779377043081,7.64156679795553,7.90659276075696,8.17138355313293),.UNSPECIFIED.);
#632=CARTESIAN_POINT('',(29.7768731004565,-3.43300169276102,-4.3688));
#633=VERTEX_POINT('',#632);
#634=EDGE_CURVE('E397',#633,#578,#631,.T.);
#635=ORIENTED_EDGE('',*,*,#634,.F.);
#636=CARTESIAN_POINT('',(26.74747,-5.39692906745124,-1.32101124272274));
#637=CARTESIAN_POINT('',(26.8292587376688,-5.37650917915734,-1.40441814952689));
#638=CARTESIAN_POINT('',(26.9109353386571,-5.35414108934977,-1.48744687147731));
#639=CARTESIAN_POINT('',(27.07389815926,-5.3054513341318,-1.65273554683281));
#640=CARTESIAN_POINT('',(27.1551843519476,-5.27912939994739,-1.73499544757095));
#641=CARTESIAN_POINT('',(27.398339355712,-5.19409989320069,-1.98073586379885));
#642=CARTESIAN_POINT('',(27.559354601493,-5.129365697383,-2.14302470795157));
#643=CARTESIAN_POINT('',(27.8742189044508,-4.98498486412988,-2.45997271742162));
#644=CARTESIAN_POINT('',(28.0281476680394,-4.90570965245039,-2.61472144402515));
#645=CARTESIAN_POINT('',(28.3313305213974,-4.73079787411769,-2.91929869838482));
#646=CARTESIAN_POINT('',(28.4805866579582,-4.63516859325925,-3.06912938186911));
#647=CARTESIAN_POINT('',(28.8322665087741,-4.38470174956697,-3.42200778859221));
#648=CARTESIAN_POINT('',(29.0318567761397,-4.22153948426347,-3.62214856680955));
#649=CARTESIAN_POINT('',(29.3201641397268,-3.94876112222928,-3.91115403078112));
#650=CARTESIAN_POINT('',(29.4151298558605,-3.85228020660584,-4.00633233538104));
#651=CARTESIAN_POINT('',(29.6000130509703,-3.64981963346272,-4.19160363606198));
#652=CARTESIAN_POINT('',(29.6899257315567,-3.54383118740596,-4.28169179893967));
#653=CARTESIAN_POINT('',(29.7768731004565,-3.43300169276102,-4.3688));
#654=B_SPLINE_CURVE_WITH_KNOTS('',3,(#636,#637,#638,#639,#640,#641,#642,#643,#644,#645,#646,
#647,#648,#649,#650,#651,#652,#653),.UNSPECIFIED.,.F.,.F.,(4,2,2,2,2,2,2,2,4),(0.,
0.355729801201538,0.711483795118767,1.42364141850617,2.11965076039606,2.8153508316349,
3.7916193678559,4.28770810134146,4.78426022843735),.UNSPECIFIED.);
#655=CARTESIAN_POINT('',(26.74747,-5.39692906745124,-1.32101124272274));
#656=VERTEX_POINT('',#655);
#657=EDGE_CURVE('E402',#656,#633,#654,.T.);
#658=ORIENTED_EDGE('',*,*,#657,.F.);
#659=CARTESIAN_POINT('',(26.74747,-5.39692906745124,1.32101124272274));
#660=VERTEX_POINT('',#659);
#661=EDGE_CURVE('E506',#656,#660,#80,.T.);
#662=ORIENTED_EDGE('',*,*,#661,.T.);
#663=CARTESIAN_POINT('',(28.0928417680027,-4.86735266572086,2.6797));
#664=CARTESIAN_POINT('',(27.9838729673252,-4.92763163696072,2.5701913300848));
#665=CARTESIAN_POINT('',(27.8738024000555,-4.98375616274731,2.45952188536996));
#666=CARTESIAN_POINT('',(27.6521437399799,-5.08776349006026,2.23644959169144));
#667=CARTESIAN_POINT('',(27.5405600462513,-5.135666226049,2.12405167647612));
#668=CARTESIAN_POINT('',(27.3160257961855,-5.22358984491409,1.89757360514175));
#669=CARTESIAN_POINT('',(27.2030752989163,-5.26361106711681,1.78349352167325));
#670=CARTESIAN_POINT('',(26.9759833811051,-5.33601334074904,1.55351390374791));
#671=CARTESIAN_POINT('',(26.8618397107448,-5.36837530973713,1.4376105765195));
#672=CARTESIAN_POINT('',(26.74747,-5.39692906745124,1.32101124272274));
#673=B_SPLINE_CURVE_WITH_KNOTS('',3,(#663,#664,#665,#666,#667,#668,#669,#670,#671,#672),
.UNSPECIFIED.,.F.,.F.,(4,2,2,2,4),(0.,0.49740472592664,0.993585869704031,1.48974564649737,
1.98712885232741),.UNSPECIFIED.);
#674=CARTESIAN_POINT('',(28.0928417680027,-4.86735266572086,2.6797));
#675=VERTEX_POINT('',#674);
#676=EDGE_CURVE('E383',#675,#660,#673,.T.);
#677=ORIENTED_EDGE('',*,*,#676,.F.);
#678=DIRECTION('',(-1.,0.,0.));
#679=VECTOR('',#678,1.);
#680=CARTESIAN_POINT('',(-12.2161702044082,-4.86735266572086,2.6797));
#681=LINE('',#680,#679);
#682=CARTESIAN_POINT('',(29.7949930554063,-4.86735266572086,2.6797));
#683=VERTEX_POINT('',#682);
#684=EDGE_CURVE('E308',#683,#675,#681,.T.);
#685=ORIENTED_EDGE('',*,*,#684,.F.);
#686=CARTESIAN_POINT('',(31.51017,-2.56152070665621,4.93057052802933));
#687=CARTESIAN_POINT('',(31.4436251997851,-2.71414164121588,4.85127048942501));
#688=CARTESIAN_POINT('',(31.3723366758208,-2.86132157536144,4.76582179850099));
#689=CARTESIAN_POINT('',(31.2221088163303,-3.14433020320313,4.58403397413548));
#690=CARTESIAN_POINT('',(31.1431799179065,-3.28017392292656,4.48770966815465));
#691=CARTESIAN_POINT('',(30.9810119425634,-3.53776494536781,4.28744714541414));
#692=CARTESIAN_POINT('',(30.8978956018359,-3.65974549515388,4.18370734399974));
#693=CARTESIAN_POINT('',(30.7274107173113,-3.89280555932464,3.96777281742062));
#694=CARTESIAN_POINT('',(30.6400413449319,-4.00388293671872,3.85557644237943));
#695=CARTESIAN_POINT('',(30.4898765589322,-4.18268389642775,3.65908300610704));
#696=CARTESIAN_POINT('',(30.4277793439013,-4.25324138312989,3.57680642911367));
#697=CARTESIAN_POINT('',(30.3028262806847,-4.38914996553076,3.40865905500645));
#698=CARTESIAN_POINT('',(30.2399706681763,-4.45450263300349,3.32278935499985));
#699=CARTESIAN_POINT('',(30.1131068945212,-4.58096419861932,3.14621352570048));
#700=CARTESIAN_POINT('',(30.0490954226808,-4.64199615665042,3.0554546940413));
#701=CARTESIAN_POINT('',(29.921492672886,-4.75873404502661,2.87024593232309));
#702=CARTESIAN_POINT('',(29.8579015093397,-4.81443857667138,2.77579504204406));
#703=CARTESIAN_POINT('',(29.7948621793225,-4.86746276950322,2.6795));
#704=B_SPLINE_CURVE_WITH_KNOTS('',3,(#686,#687,#688,#689,#690,#691,#692,#693,#694,#695,#696,
#697,#698,#699,#700,#701,#702,#703),.UNSPECIFIED.,.F.,.F.,(4,2,2,2,2,2,2,2,4),(0.,
0.552799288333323,1.10485380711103,1.64550300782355,2.18625796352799,2.56085379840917,
2.93533607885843,3.31534963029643,3.69546268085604),.UNSPECIFIED.);
#705=EDGE_CURVE('E343',#474,#683,#704,.T.);
#706=ORIENTED_EDGE('',*,*,#705,.F.);
#707=ORIENTED_EDGE('',*,*,#514,.F.);
#708=EDGE_LOOP('',(#542,#543,#556,#557,#580,#635,#658,#662,#677,#685,#706,#707));
#709=FACE_BOUND('',#708,.T.);
#710=ADVANCED_FACE('F374',(#709),#523,.F.);
#711=DIRECTION('',(0.,0.,1.));
#712=VECTOR('',#711,1.);
#713=CARTESIAN_POINT('',(26.74747,-5.39692906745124,12.7));
#714=LINE('',#713,#712);
#715=EDGE_CURVE('E322',#660,#656,#714,.F.);
#716=ORIENTED_EDGE('',*,*,#715,.F.);
#717=ORIENTED_EDGE('',*,*,#661,.F.);
#718=EDGE_LOOP('',(#716,#717));
#719=FACE_BOUND('',#718,.T.);
#720=ADVANCED_FACE('F279',(#719),#65,.T.);
#721=CARTESIAN_POINT('',(8.128,0.,-12.7));
#722=DIRECTION('',(0.,0.,-1.));
#723=DIRECTION('',(0.,1.,0.));
#724=AXIS2_PLACEMENT_3D('',#721,#722,#723);
#725=CYLINDRICAL_SURFACE('',#724,5.5626);
#726=CARTESIAN_POINT('',(8.128,0.,-2.6797));
#727=DIRECTION('',(0.,0.,-1.));
#728=DIRECTION('',(0.,1.,0.));
#729=AXIS2_PLACEMENT_3D('',#726,#727,#728);
#730=CIRCLE('',#729,5.5626);
#731=CARTESIAN_POINT('',(12.8579401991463,-2.92748774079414,-2.6797));
#732=VERTEX_POINT('',#731);
#733=CARTESIAN_POINT('',(12.8579401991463,2.92748774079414,-2.6797));
#734=VERTEX_POINT('',#733);
#735=EDGE_CURVE('E196',#732,#734,#730,.T.);
#736=ORIENTED_EDGE('',*,*,#735,.T.);
#737=CARTESIAN_POINT('',(12.8579401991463,2.92748774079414,-2.6797));
#738=CARTESIAN_POINT('',(12.8056444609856,3.01201722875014,-2.58731274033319));
#739=CARTESIAN_POINT('',(12.7529209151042,3.09210281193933,-2.49108487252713));
#740=CARTESIAN_POINT('',(12.6487984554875,3.24239745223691,-2.29201169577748));
#741=CARTESIAN_POINT('',(12.5973921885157,3.31268279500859,-2.18922777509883));
#742=CARTESIAN_POINT('',(12.497149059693,3.44381508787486,-1.97654257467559));
#743=CARTESIAN_POINT('',(12.4483128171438,3.50465976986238,-1.8666395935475));
#744=CARTESIAN_POINT('',(12.3549553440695,3.61673638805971,-1.6390163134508));
#745=CARTESIAN_POINT('',(12.3104735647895,3.66788378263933,-1.52123838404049));
#746=CARTESIAN_POINT('',(12.26947,3.71358923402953,-1.40008269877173));
#747=B_SPLINE_CURVE_WITH_KNOTS('',3,(#737,#738,#739,#740,#741,#742,#743,#744,#745,#746),
.UNSPECIFIED.,.F.,.F.,(4,2,2,2,4),(0.,0.406999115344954,0.810628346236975,1.21435439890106,
1.62145281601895),.UNSPECIFIED.);
#748=CARTESIAN_POINT('',(12.26947,3.71358923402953,-1.40008269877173));
#749=VERTEX_POINT('',#748);
#750=EDGE_CURVE('E187',#734,#749,#747,.T.);
#751=ORIENTED_EDGE('',*,*,#750,.T.);
#752=DIRECTION('',(0.,0.,-1.));
#753=VECTOR('',#752,1.);
#754=CARTESIAN_POINT('',(12.26947,3.71358923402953,-12.7));
#755=LINE('',#754,#753);
#756=CARTESIAN_POINT('',(12.26947,3.71358923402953,1.40008269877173));
#757=VERTEX_POINT('',#756);
#758=EDGE_CURVE('E11',#749,#757,#755,.F.);
#759=ORIENTED_EDGE('',*,*,#758,.T.);
#760=CARTESIAN_POINT('',(12.26947,3.71358923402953,1.40008269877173));
#761=CARTESIAN_POINT('',(12.3104735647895,3.66788378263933,1.52123838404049));
#762=CARTESIAN_POINT('',(12.3549553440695,3.61673638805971,1.6390163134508));
#763=CARTESIAN_POINT('',(12.4483128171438,3.50465976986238,1.8666395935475));
#764=CARTESIAN_POINT('',(12.497149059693,3.44381508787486,1.97654257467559));
#765=CARTESIAN_POINT('',(12.5973921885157,3.31268279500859,2.18922777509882));
#766=CARTESIAN_POINT('',(12.6487984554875,3.24239745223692,2.29201169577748));
#767=CARTESIAN_POINT('',(12.7529209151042,3.09210281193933,2.49108487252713));
#768=CARTESIAN_POINT('',(12.8056444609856,3.01201722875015,2.58731274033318));
#769=CARTESIAN_POINT('',(12.8579401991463,2.92748774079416,2.67969999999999));
#770=B_SPLINE_CURVE_WITH_KNOTS('',3,(#760,#761,#762,#763,#764,#765,#766,#767,#768,#769),
.UNSPECIFIED.,.F.,.F.,(4,2,2,2,4),(0.,0.407098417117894,0.810824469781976,1.214453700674,
1.62145281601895),.UNSPECIFIED.);
#771=CARTESIAN_POINT('',(12.8579401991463,2.92748774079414,2.6797));
#772=VERTEX_POINT('',#771);
#773=EDGE_CURVE('E189',#757,#772,#770,.T.);
#774=ORIENTED_EDGE('',*,*,#773,.T.);
#775=CARTESIAN_POINT('',(8.128,0.,2.6797));
#776=DIRECTION('',(0.,0.,1.));
#777=DIRECTION('',(1.,0.,0.));
#778=AXIS2_PLACEMENT_3D('',#775,#776,#777);
#779=CIRCLE('',#778,5.56260000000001);
#780=CARTESIAN_POINT('',(12.8579401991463,-2.92748774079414,2.6797));
#781=VERTEX_POINT('',#780);
#782=EDGE_CURVE('E681',#772,#781,#779,.T.);
#783=ORIENTED_EDGE('',*,*,#782,.T.);
#784=CARTESIAN_POINT('',(12.8579401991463,-2.92748774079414,2.6797));
#785=CARTESIAN_POINT('',(12.8056444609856,-3.01201722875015,2.58731274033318));
#786=CARTESIAN_POINT('',(12.7529209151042,-3.09210281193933,2.49108487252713));
#787=CARTESIAN_POINT('',(12.6487984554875,-3.24239745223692,2.29201169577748));
#788=CARTESIAN_POINT('',(12.5973921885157,-3.31268279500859,2.18922777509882));
#789=CARTESIAN_POINT('',(12.497149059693,-3.44381508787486,1.97654257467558));
#790=CARTESIAN_POINT('',(12.4483128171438,-3.50465976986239,1.86663959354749));
#791=CARTESIAN_POINT('',(12.3549553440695,-3.61673638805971,1.63901631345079));
#792=CARTESIAN_POINT('',(12.3104735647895,-3.66788378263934,1.52123838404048));
#793=CARTESIAN_POINT('',(12.26947,-3.71358923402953,1.40008269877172));
#794=B_SPLINE_CURVE_WITH_KNOTS('',3,(#784,#785,#786,#787,#788,#789,#790,#791,#792,#793),
.UNSPECIFIED.,.F.,.F.,(4,2,2,2,4),(0.,0.406999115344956,0.810628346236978,1.21435439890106,
1.62145281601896),.UNSPECIFIED.);
#795=CARTESIAN_POINT('',(12.26947,-3.71358923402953,1.40008269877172));
#796=VERTEX_POINT('',#795);
#797=EDGE_CURVE('E244',#781,#796,#794,.T.);
#798=ORIENTED_EDGE('',*,*,#797,.T.);
#799=DIRECTION('',(0.,0.,-1.));
#800=VECTOR('',#799,1.);
#801=CARTESIAN_POINT('',(12.26947,-3.71358923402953,-12.7));
#802=LINE('',#801,#800);
#803=CARTESIAN_POINT('',(12.26947,-3.71358923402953,-1.40008269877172));
#804=VERTEX_POINT('',#803);
#805=EDGE_CURVE('E43',#796,#804,#802,.T.);
#806=ORIENTED_EDGE('',*,*,#805,.T.);
#807=CARTESIAN_POINT('',(12.26947,-3.71358923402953,-1.40008269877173));
#808=CARTESIAN_POINT('',(12.3104735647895,-3.66788378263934,-1.52123838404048));
#809=CARTESIAN_POINT('',(12.3549553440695,-3.61673638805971,-1.63901631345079));
#810=CARTESIAN_POINT('',(12.4483128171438,-3.50465976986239,-1.86663959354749));
#811=CARTESIAN_POINT('',(12.497149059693,-3.44381508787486,-1.97654257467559));
#812=CARTESIAN_POINT('',(12.5973921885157,-3.31268279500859,-2.18922777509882));
#813=CARTESIAN_POINT('',(12.6487984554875,-3.24239745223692,-2.29201169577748));
#814=CARTESIAN_POINT('',(12.7529209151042,-3.09210281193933,-2.49108487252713));
#815=CARTESIAN_POINT('',(12.8056444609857,-3.01201722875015,-2.58731274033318));
#816=CARTESIAN_POINT('',(12.8579401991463,-2.92748774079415,-2.6797));
#817=B_SPLINE_CURVE_WITH_KNOTS('',3,(#807,#808,#809,#810,#811,#812,#813,#814,#815,#816),
.UNSPECIFIED.,.F.,.F.,(4,2,2,2,4),(0.,0.407098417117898,0.810824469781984,1.21445370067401,
1.62145281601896),.UNSPECIFIED.);
#818=EDGE_CURVE('E255',#804,#732,#817,.T.);
#819=ORIENTED_EDGE('',*,*,#818,.T.);
#820=EDGE_LOOP('',(#736,#751,#759,#774,#783,#798,#806,#819));
#821=FACE_BOUND('',#820,.T.);
#822=ADVANCED_FACE('F193',(#821),#725,.F.);
#823=CARTESIAN_POINT('',(13.6906,0.,-2.6797));
#824=DIRECTION('',(0.,0.,1.));
#825=DIRECTION('',(0.,-1.,0.));
#826=AXIS2_PLACEMENT_3D('',#823,#824,#825);
#827=PLANE('',#826);
#828=ORIENTED_EDGE('',*,*,#735,.F.);
#829=DIRECTION('',(1.,0.,0.));
#830=VECTOR('',#829,1.);
#831=CARTESIAN_POINT('',(39.44747,-2.92748774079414,-2.6797));
#832=LINE('',#831,#830);
#833=CARTESIAN_POINT('',(13.996296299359,-2.92748774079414,-2.6797));
#834=VERTEX_POINT('',#833);
#835=EDGE_CURVE('E265',#732,#834,#832,.T.);
#836=ORIENTED_EDGE('',*,*,#835,.T.);
#837=CARTESIAN_POINT('',(8.128,0.,-2.6797));
#838=DIRECTION('',(0.,0.,-1.));
#839=DIRECTION('',(0.,1.,0.));
#840=AXIS2_PLACEMENT_3D('',#837,#838,#839);
#841=CIRCLE('',#840,6.55797879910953);
#842=CARTESIAN_POINT('',(13.996296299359,2.92748774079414,-2.6797));
#843=VERTEX_POINT('',#842);
#844=EDGE_CURVE('E508',#834,#843,#841,.T.);
#845=ORIENTED_EDGE('',*,*,#844,.T.);
#846=DIRECTION('',(1.,0.,0.));
#847=VECTOR('',#846,1.);
#848=CARTESIAN_POINT('',(39.44747,2.92748774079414,-2.6797));
#849=LINE('',#848,#847);
#850=EDGE_CURVE('E198',#843,#734,#849,.F.);
#851=ORIENTED_EDGE('',*,*,#850,.T.);
#852=EDGE_LOOP('',(#828,#836,#845,#851));
#853=FACE_BOUND('',#852,.T.);
#854=ADVANCED_FACE('F271',(#853),#827,.F.);
#855=CARTESIAN_POINT('',(8.128,0.,-12.7));
#856=DIRECTION('',(0.,0.,-1.));
#857=DIRECTION('',(0.,1.,0.));
#858=AXIS2_PLACEMENT_3D('',#855,#856,#857);
#859=CONICAL_SURFACE('',#858,6.858,0.0299323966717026);
#860=ORIENTED_EDGE('',*,*,#844,.F.);
#861=CARTESIAN_POINT('',(13.9961982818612,-2.92767079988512,-2.6795));
#862=CARTESIAN_POINT('',(14.0353597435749,-2.85454905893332,-2.7593870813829));
#863=CARTESIAN_POINT('',(14.0743107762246,-2.7781013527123,-2.83635574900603));
#864=CARTESIAN_POINT('',(14.1509987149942,-2.61877561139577,-2.98409314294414));
#865=CARTESIAN_POINT('',(14.1887348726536,-2.53589371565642,-3.05485809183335));
#866=CARTESIAN_POINT('',(14.2624104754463,-2.36340150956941,-3.19020500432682));
#867=CARTESIAN_POINT('',(14.2983352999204,-2.27374769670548,-3.25473961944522));
#868=CARTESIAN_POINT('',(14.36728774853,-2.08859219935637,-3.37654207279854));
#869=CARTESIAN_POINT('',(14.4003158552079,-1.99309149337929,-3.43381112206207));
#870=CARTESIAN_POINT('',(14.4628419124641,-1.79621765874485,-3.54078869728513));
#871=CARTESIAN_POINT('',(14.4923230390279,-1.69481968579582,-3.59046147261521));
#872=CARTESIAN_POINT('',(14.5468203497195,-1.48714488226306,-3.68133388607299));
#873=CARTESIAN_POINT('',(14.5718371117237,-1.38086868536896,-3.7225346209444));
#874=CARTESIAN_POINT('',(14.6166486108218,-1.16451545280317,-3.7957714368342));
#875=CARTESIAN_POINT('',(14.6364596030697,-1.05445149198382,-3.82783607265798));
#876=CARTESIAN_POINT('',(14.6703758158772,-0.831131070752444,-3.88244827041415));
#877=CARTESIAN_POINT('',(14.6844819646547,-0.717875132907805,-3.90499738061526));
#878=CARTESIAN_POINT('',(14.705315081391,-0.502058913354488,-3.93820567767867));
#879=CARTESIAN_POINT('',(14.7126916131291,-0.399721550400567,-3.94991374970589));
#880=CARTESIAN_POINT('',(14.7224150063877,-0.194213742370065,-3.96533401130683));
#881=CARTESIAN_POINT('',(14.7247623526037,-0.0910433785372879,-3.96904697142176));
#882=CARTESIAN_POINT('',(14.7243636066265,0.1152983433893,-3.96841596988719));
#883=CARTESIAN_POINT('',(14.7216160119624,0.218469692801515,-3.96406963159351));
#884=CARTESIAN_POINT('',(14.7111063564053,0.423877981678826,-3.94739645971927));
#885=CARTESIAN_POINT('',(14.7033444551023,0.526114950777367,-3.93506988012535));
#886=CARTESIAN_POINT('',(14.6744558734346,0.813692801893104,-3.88900261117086));
#887=CARTESIAN_POINT('',(14.6475810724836,0.997072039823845,-3.84597487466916));
#888=CARTESIAN_POINT('',(14.5796655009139,1.35341922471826,-3.73552214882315));
#889=CARTESIAN_POINT('',(14.5386207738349,1.52638424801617,-3.66809034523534));
#890=CARTESIAN_POINT('',(14.4422881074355,1.86972678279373,-3.5062028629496));
#891=CARTESIAN_POINT('',(14.3862406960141,2.03918522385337,-3.41026101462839));
#892=CARTESIAN_POINT('',(14.2655350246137,2.36015651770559,-3.19653083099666));
#893=CARTESIAN_POINT('',(14.2008808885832,2.51167789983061,-3.07875294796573));
#894=CARTESIAN_POINT('',(14.1114970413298,2.70138241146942,-2.90821063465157));
#895=CARTESIAN_POINT('',(14.0886166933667,2.74829708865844,-2.86391334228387));
#896=CARTESIAN_POINT('',(14.0425824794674,2.83974577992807,-2.77325644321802));
#897=CARTESIAN_POINT('',(14.0194292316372,2.88428424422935,-2.72690101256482));
#898=CARTESIAN_POINT('',(13.9961982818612,2.92767079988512,-2.6795));
#899=B_SPLINE_CURVE_WITH_KNOTS('',3,(#861,#862,#863,#864,#865,#866,#867,#868,#869,#870,#871,
#872,#873,#874,#875,#876,#877,#878,#879,#880,#881,#882,#883,#884,#885,#886,#887,#888,#889,#890,
#891,#892,#893,#894,#895,#896,#897,#898),.UNSPECIFIED.,.F.,.F.,(4,2,2,2,2,2,2,2,2,2,2,2,2,2,2,2,
2,2,4),(0.,0.345426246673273,0.691061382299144,1.03914485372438,1.38717022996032,
1.73678621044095,2.08635690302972,2.43482272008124,2.78323181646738,3.09261553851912,
3.40196944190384,3.71141458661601,4.02084988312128,4.58891497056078,5.15713879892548,
5.76275031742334,6.3680726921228,6.57340116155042,6.77833051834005),.UNSPECIFIED.);
#900=EDGE_CURVE('E203',#834,#843,#899,.T.);
#901=ORIENTED_EDGE('',*,*,#900,.T.);
#902=EDGE_LOOP('',(#860,#901));
#903=FACE_BOUND('',#902,.T.);
#904=ORIENTED_EDGE('',*,*,#294,.T.);
#905=EDGE_LOOP('',(#904));
#906=FACE_BOUND('',#905,.T.);
#907=ADVANCED_FACE('F266',(#903,#906),#859,.F.);
#908=CARTESIAN_POINT('',(25.4,0.,-4.3688));
#909=DIRECTION('',(0.,0.,1.));
#910=DIRECTION('',(1.,0.,0.));
#911=AXIS2_PLACEMENT_3D('',#908,#909,#910);
#912=CONICAL_SURFACE('',#911,5.56260000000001,1.02974425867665);
#913=ORIENTED_EDGE('',*,*,#634,.T.);
#914=CARTESIAN_POINT('',(25.4,0.,-4.3688));
#915=DIRECTION('',(0.,0.,1.));
#916=DIRECTION('',(1.,0.,0.));
#917=AXIS2_PLACEMENT_3D('',#914,#915,#916);
#918=CIRCLE('',#917,5.56260000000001);
#919=EDGE_CURVE('E315',#578,#633,#918,.T.);
#920=ORIENTED_EDGE('',*,*,#919,.T.);
#921=EDGE_LOOP('',(#913,#920));
#922=FACE_BOUND('',#921,.T.);
#923=CARTESIAN_POINT('',(25.4,0.,-7.71114727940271));
#924=VERTEX_POINT('',#923);
#925=VERTEX_LOOP('',#924);
#926=FACE_BOUND('',#925,.T.);
#927=ADVANCED_FACE('F270',(#922,#926),#912,.F.);
#928=CARTESIAN_POINT('',(25.4,0.,12.7));
#929=DIRECTION('',(0.,0.,1.));
#930=DIRECTION('',(1.,0.,0.));
#931=AXIS2_PLACEMENT_3D('',#928,#929,#930);
#932=CYLINDRICAL_SURFACE('',#931,5.56260000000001);
#933=ORIENTED_EDGE('',*,*,#50,.T.);
#934=CARTESIAN_POINT('',(20.6700598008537,2.92748774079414,2.6797));
#935=CARTESIAN_POINT('',(20.7152525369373,3.0005263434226,2.59988183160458));
#936=CARTESIAN_POINT('',(20.7607533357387,3.07024114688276,2.51719230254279));
#937=CARTESIAN_POINT('',(20.851312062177,3.20287073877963,2.34613717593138));
#938=CARTESIAN_POINT('',(20.8963694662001,3.26577820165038,2.25776562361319));
#939=CARTESIAN_POINT('',(20.9853899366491,3.38516613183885,2.07453710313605));
#940=CARTESIAN_POINT('',(21.029334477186,3.44156443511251,1.97961727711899));
#941=CARTESIAN_POINT('',(21.114207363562,3.54669766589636,1.78443626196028));
#942=CARTESIAN_POINT('',(21.1551371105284,3.59543616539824,1.68417759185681));
#943=CARTESIAN_POINT('',(21.253679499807,3.7092988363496,1.4220210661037));
#944=CARTESIAN_POINT('',(21.3081900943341,3.76882789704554,1.25637246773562));
#945=CARTESIAN_POINT('',(21.3769117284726,3.84166572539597,1.00022060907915));
#946=CARTESIAN_POINT('',(21.3976216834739,3.86318061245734,0.913704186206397));
#947=CARTESIAN_POINT('',(21.4339614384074,3.90047880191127,0.738415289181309));
#948=CARTESIAN_POINT('',(21.4495940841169,3.91626531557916,0.6496441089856));
#949=CARTESIAN_POINT('',(21.4752340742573,3.94196245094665,0.469357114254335));
#950=CARTESIAN_POINT('',(21.4851731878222,3.95180187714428,0.377821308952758));
#951=CARTESIAN_POINT('',(21.4986299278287,3.96508774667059,0.193812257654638));
#952=CARTESIAN_POINT('',(21.502147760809,3.96853439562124,0.101339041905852));
#953=CARTESIAN_POINT('',(21.5025664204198,3.96894593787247,-0.0836697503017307));
#954=CARTESIAN_POINT('',(21.4994652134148,3.9659088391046,-0.176205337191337));
#955=CARTESIAN_POINT('',(21.4868235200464,3.95343401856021,-0.360371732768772));
#956=CARTESIAN_POINT('',(21.477283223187,3.94399648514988,-0.452002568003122));
#957=CARTESIAN_POINT('',(21.4432628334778,3.9099494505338,-0.698510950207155));
#958=CARTESIAN_POINT('',(21.4129788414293,3.87931774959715,-0.851808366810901));
#959=CARTESIAN_POINT('',(21.3386936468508,3.80146992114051,-1.1505420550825));
#960=CARTESIAN_POINT('',(21.2946793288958,3.75423793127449,-1.29597065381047));
#961=CARTESIAN_POINT('',(21.1721011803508,3.61657482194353,-1.65039614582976));
#962=CARTESIAN_POINT('',(21.0874176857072,3.51642307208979,-1.85356230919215));
#963=CARTESIAN_POINT('',(20.9537564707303,3.34347477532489,-2.14119769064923));
#964=CARTESIAN_POINT('',(20.9080253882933,3.2819324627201,-2.23434676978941));
#965=CARTESIAN_POINT('',(20.8155747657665,3.1514990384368,-2.41483223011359));
#966=CARTESIAN_POINT('',(20.7688553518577,3.08260886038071,-2.50216934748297));
#967=CARTESIAN_POINT('',(20.6271428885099,2.8623700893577,-2.7584873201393));
#968=CARTESIAN_POINT('',(20.5323920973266,2.69967080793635,-2.91808745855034));
#969=CARTESIAN_POINT('',(20.3526149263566,2.34641572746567,-3.2089768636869));
#970=CARTESIAN_POINT('',(20.2675728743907,2.15590598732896,-3.34031206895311));
#971=CARTESIAN_POINT('',(20.128690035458,1.78539379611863,-3.54966762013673));
#972=CARTESIAN_POINT('',(20.0719905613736,1.60951846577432,-3.63301228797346));
#973=CARTESIAN_POINT('',(19.9991786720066,1.33515853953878,-3.73871205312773));
#974=CARTESIAN_POINT('',(19.9769434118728,1.24192182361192,-3.77073157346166));
#975=CARTESIAN_POINT('',(19.9370125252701,1.05244512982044,-3.82793847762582));
#976=CARTESIAN_POINT('',(19.9193149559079,0.956206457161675,-3.85312878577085));
#977=CARTESIAN_POINT('',(19.8887723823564,0.760747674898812,-3.89645024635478));
#978=CARTESIAN_POINT('',(19.8759584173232,0.661512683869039,-3.914536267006));
#979=CARTESIAN_POINT('',(19.8556625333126,0.461456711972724,-3.94312534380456));
#980=CARTESIAN_POINT('',(19.8481782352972,0.36063645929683,-3.95363178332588));
#981=CARTESIAN_POINT('',(19.8387282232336,0.158234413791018,-3.9668908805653));
#982=CARTESIAN_POINT('',(19.8367621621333,0.0566526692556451,-3.96964402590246));
#983=CARTESIAN_POINT('',(19.8383996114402,-0.146371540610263,-3.9673489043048));
#984=CARTESIAN_POINT('',(19.8420027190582,-0.24781401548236,-3.96230120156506));
#985=CARTESIAN_POINT('',(19.8540771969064,-0.440028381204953,-3.94534527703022));
#986=CARTESIAN_POINT('',(19.8620508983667,-0.530894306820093,-3.93413811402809));
#987=CARTESIAN_POINT('',(19.8823022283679,-0.711179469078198,-3.90557865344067));
#988=CARTESIAN_POINT('',(19.8945812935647,-0.800598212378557,-3.88822430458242));
#989=CARTESIAN_POINT('',(19.9375259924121,-1.06576438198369,-3.82726240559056));
#990=CARTESIAN_POINT('',(19.9743092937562,-1.23857436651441,-3.77474207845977));
#991=CARTESIAN_POINT('',(20.063132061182,-1.57877490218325,-3.64593864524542));
#992=CARTESIAN_POINT('',(20.1157031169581,-1.7457025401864,-3.56882050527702));
#993=CARTESIAN_POINT('',(20.2318765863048,-2.06441359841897,-3.39443457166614));
#994=CARTESIAN_POINT('',(20.2954808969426,-2.21619440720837,-3.29716331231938));
#995=CARTESIAN_POINT('',(20.4407556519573,-2.52631453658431,-3.06784650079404));
#996=CARTESIAN_POINT('',(20.5236862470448,-2.68177881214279,-2.93272392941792));
#997=CARTESIAN_POINT('',(20.6933444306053,-2.96948423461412,-2.64106585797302));
#998=CARTESIAN_POINT('',(20.7800801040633,-3.10167261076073,-2.48448309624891));
#999=CARTESIAN_POINT('',(20.9146293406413,-3.29109524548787,-2.22123581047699));
#1000=CARTESIAN_POINT('',(20.9635786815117,-3.35658620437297,-2.12101324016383));
#1001=CARTESIAN_POINT('',(21.0587066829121,-3.47874852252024,-1.91409585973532));
#1002=CARTESIAN_POINT('',(21.1048844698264,-3.53541710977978,-1.80739902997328));
#1003=CARTESIAN_POINT('',(21.2362492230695,-3.69107162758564,-1.47835173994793));
#1004=CARTESIAN_POINT('',(21.3147402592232,-3.77633597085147,-1.24618021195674));
#1005=CARTESIAN_POINT('',(21.4136523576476,-3.88004373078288,-0.84953091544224));
#1006=CARTESIAN_POINT('',(21.4448102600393,-3.91150851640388,-0.691085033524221));
#1007=CARTESIAN_POINT('',(21.4881609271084,-3.95487137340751,-0.369091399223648));
#1008=CARTESIAN_POINT('',(21.5003882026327,-3.96680505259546,-0.205553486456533));
#1009=CARTESIAN_POINT('',(21.5039019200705,-3.97025879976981,0.122344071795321));
#1010=CARTESIAN_POINT('',(21.4951401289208,-3.96173184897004,0.286704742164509));
#1011=CARTESIAN_POINT('',(21.4580716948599,-3.92483839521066,0.611023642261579));
#1012=CARTESIAN_POINT('',(21.4297362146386,-3.8964426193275,0.770975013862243));
#1013=CARTESIAN_POINT('',(21.3479640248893,-3.81153730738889,1.12449351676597));
#1014=CARTESIAN_POINT('',(21.2898442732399,-3.74954437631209,1.31562796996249));
#1015=CARTESIAN_POINT('',(21.1583217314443,-3.60007763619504,1.68219844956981));
#1016=CARTESIAN_POINT('',(21.084882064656,-3.5125421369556,1.85759510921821));
#1017=CARTESIAN_POINT('',(20.9534458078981,-3.34343988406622,2.1427308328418));
#1018=CARTESIAN_POINT('',(20.8971784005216,-3.26755569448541,2.25671792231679));
#1019=CARTESIAN_POINT('',(20.7837877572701,-3.10530053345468,2.47515397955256));
#1020=CARTESIAN_POINT('',(20.726672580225,-3.01900178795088,2.57966072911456));
#1021=CARTESIAN_POINT('',(20.6700598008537,-2.92748774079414,2.6797));
#1022=B_SPLINE_CURVE_WITH_KNOTS('',3,(#934,#935,#936,#937,#938,#939,#940,#941,#942,#943,#944,
#945,#946,#947,#948,#949,#950,#951,#952,#953,#954,#955,#956,#957,#958,#959,#960,#961,#962,#963,
#964,#965,#966,#967,#968,#969,#970,#971,#972,#973,#974,#975,#976,#977,#978,#979,#980,#981,#982,
#983,#984,#985,#986,#987,#988,#989,#990,#991,#992,#993,#994,#995,#996,#997,#998,#999,#1000,
#1001,#1002,#1003,#1004,#1005,#1006,#1007,#1008,#1009,#1010,#1011,#1012,#1013,#1014,#1015,#1016,
#1017,#1018,#1019,#1020,#1021),.UNSPECIFIED.,.F.,.F.,(4,2,2,2,2,2,2,2,2,2,2,2,2,2,2,2,2,2,2,2,2,
2,2,2,2,2,2,2,2,2,2,2,2,2,2,2,2,2,2,2,2,2,2,4),(0.,0.351675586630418,0.703725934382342,
1.05982191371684,1.41575133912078,1.96613375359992,2.24043148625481,2.51457521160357,
2.79193899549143,3.06929385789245,3.3467339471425,3.62416587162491,4.09978775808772,
4.57586536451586,5.29710693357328,5.65878105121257,6.0204092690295,6.75750212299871,
7.49338779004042,8.09878371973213,8.40163903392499,8.70436445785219,9.00898306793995,
9.31346561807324,9.61792901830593,9.92237039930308,10.1977437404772,10.4732090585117,
11.0236845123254,11.5952978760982,12.1670096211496,12.8307217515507,13.4959197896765,
13.8834843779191,14.2711704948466,15.0430808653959,15.5346981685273,16.0254181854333,
16.5172669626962,17.0098419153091,17.633984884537,18.2596479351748,18.7031474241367,
19.1437311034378),.UNSPECIFIED.);
#1023=CARTESIAN_POINT('',(20.6700598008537,-2.92748774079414,2.6797));
#1024=VERTEX_POINT('',#1023);
#1025=EDGE_CURVE('E230',#40,#1024,#1022,.T.);
#1026=ORIENTED_EDGE('',*,*,#1025,.T.);
#1027=EDGE_CURVE('E304',#1024,#675,#47,.T.);
#1028=ORIENTED_EDGE('',*,*,#1027,.T.);
#1029=ORIENTED_EDGE('',*,*,#676,.T.);
#1030=ORIENTED_EDGE('',*,*,#715,.T.);
#1031=ORIENTED_EDGE('',*,*,#657,.T.);
#1032=ORIENTED_EDGE('',*,*,#919,.F.);
#1033=ORIENTED_EDGE('',*,*,#579,.T.);
#1034=ORIENTED_EDGE('',*,*,#74,.T.);
#1035=ORIENTED_EDGE('',*,*,#555,.T.);
#1036=EDGE_LOOP('',(#933,#1026,#1028,#1029,#1030,#1031,#1032,#1033,#1034,#1035));
#1037=FACE_BOUND('',#1036,.T.);
#1038=ADVANCED_FACE('F293',(#1037),#932,.F.);
#1039=ORIENTED_EDGE('',*,*,#1027,.F.);
#1040=DIRECTION('',(1.,0.,0.));
#1041=VECTOR('',#1040,1.);
#1042=CARTESIAN_POINT('',(39.44747,-2.92748774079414,2.6797));
#1043=LINE('',#1042,#1041);
#1044=CARTESIAN_POINT('',(19.531703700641,-2.92748774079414,2.6797));
#1045=VERTEX_POINT('',#1044);
#1046=EDGE_CURVE('E305',#1024,#1045,#1043,.F.);
#1047=ORIENTED_EDGE('',*,*,#1046,.T.);
#1048=EDGE_CURVE('E316',#1045,#683,#28,.T.);
#1049=ORIENTED_EDGE('',*,*,#1048,.T.);
#1050=ORIENTED_EDGE('',*,*,#684,.T.);
#1051=EDGE_LOOP('',(#1039,#1047,#1049,#1050));
#1052=FACE_BOUND('',#1051,.T.);
#1053=ADVANCED_FACE('F284',(#1052),#23,.F.);
#1054=CARTESIAN_POINT('',(25.4,0.,12.7));
#1055=DIRECTION('',(0.,0.,1.));
#1056=DIRECTION('',(1.,0.,0.));
#1057=AXIS2_PLACEMENT_3D('',#1054,#1055,#1056);
#1058=CONICAL_SURFACE('',#1057,6.858,0.0299323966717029);
#1059=ORIENTED_EDGE('',*,*,#1048,.F.);
#1060=CARTESIAN_POINT('',(19.5318017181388,-2.92767079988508,2.67950000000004));
#1061=CARTESIAN_POINT('',(19.4926402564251,-2.85454905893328,2.75938708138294));
#1062=CARTESIAN_POINT('',(19.4536892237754,-2.77810135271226,2.83635574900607));
#1063=CARTESIAN_POINT('',(19.3770012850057,-2.61877561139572,2.98409314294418));
#1064=CARTESIAN_POINT('',(19.3392651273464,-2.53589371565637,3.05485809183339));
#1065=CARTESIAN_POINT('',(19.2655895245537,-2.36340150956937,3.19020500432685));
#1066=CARTESIAN_POINT('',(19.2296647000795,-2.27374769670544,3.25473961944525));
#1067=CARTESIAN_POINT('',(19.16071225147,-2.08859219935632,3.37654207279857));
#1068=CARTESIAN_POINT('',(19.1276841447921,-1.99309149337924,3.4338111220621));
#1069=CARTESIAN_POINT('',(19.0651580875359,-1.79621765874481,3.54078869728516));
#1070=CARTESIAN_POINT('',(19.0356769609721,-1.69481968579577,3.59046147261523));
#1071=CARTESIAN_POINT('',(18.9811796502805,-1.48714488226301,3.68133388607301));
#1072=CARTESIAN_POINT('',(18.9561628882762,-1.38086868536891,3.72253462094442));
#1073=CARTESIAN_POINT('',(18.9113513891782,-1.16451545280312,3.79577143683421));
#1074=CARTESIAN_POINT('',(18.8915403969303,-1.05445149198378,3.82783607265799));
#1075=CARTESIAN_POINT('',(18.8576241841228,-0.831131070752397,3.88244827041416));
#1076=CARTESIAN_POINT('',(18.8435180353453,-0.717875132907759,3.90499738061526));
#1077=CARTESIAN_POINT('',(18.8226849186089,-0.502058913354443,3.93820567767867));
#1078=CARTESIAN_POINT('',(18.8153083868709,-0.399721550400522,3.94991374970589));
#1079=CARTESIAN_POINT('',(18.8055849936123,-0.19421374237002,3.96533401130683));
#1080=CARTESIAN_POINT('',(18.8032376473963,-0.0910433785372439,3.96904697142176));
#1081=CARTESIAN_POINT('',(18.8036363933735,0.115298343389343,3.96841596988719));
#1082=CARTESIAN_POINT('',(18.8063839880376,0.218469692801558,3.96406963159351));
#1083=CARTESIAN_POINT('',(18.8168936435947,0.423877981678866,3.94739645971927));
#1084=CARTESIAN_POINT('',(18.8246555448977,0.526114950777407,3.93506988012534));
#1085=CARTESIAN_POINT('',(18.8535441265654,0.813692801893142,3.88900261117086));
#1086=CARTESIAN_POINT('',(18.8804189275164,0.997072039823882,3.84597487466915));
#1087=CARTESIAN_POINT('',(18.9483344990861,1.35341922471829,3.73552214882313));
#1088=CARTESIAN_POINT('',(18.9893792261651,1.52638424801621,3.66809034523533));
#1089=CARTESIAN_POINT('',(19.0857118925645,1.86972678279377,3.50620286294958));
#1090=CARTESIAN_POINT('',(19.1417593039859,2.0391852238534,3.41026101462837));
#1091=CARTESIAN_POINT('',(19.2624649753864,2.36015651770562,3.19653083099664));
#1092=CARTESIAN_POINT('',(19.3271191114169,2.51167789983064,3.07875294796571));
#1093=CARTESIAN_POINT('',(19.4165029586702,2.70138241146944,2.90821063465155));
#1094=CARTESIAN_POINT('',(19.4393833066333,2.74829708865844,2.86391334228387));
#1095=CARTESIAN_POINT('',(19.4854175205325,2.83974577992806,2.77325644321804));
#1096=CARTESIAN_POINT('',(19.5085707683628,2.88428424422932,2.72690101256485));
#1097=CARTESIAN_POINT('',(19.5318017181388,2.92767079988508,2.67950000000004));
#1098=B_SPLINE_CURVE_WITH_KNOTS('',3,(#1060,#1061,#1062,#1063,#1064,#1065,#1066,#1067,#1068,
#1069,#1070,#1071,#1072,#1073,#1074,#1075,#1076,#1077,#1078,#1079,#1080,#1081,#1082,#1083,#1084,
#1085,#1086,#1087,#1088,#1089,#1090,#1091,#1092,#1093,#1094,#1095,#1096,#1097),.UNSPECIFIED.,
.F.,.F.,(4,2,2,2,2,2,2,2,2,2,2,2,2,2,2,2,2,2,4),(0.,0.345426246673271,0.691061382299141,
1.03914485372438,1.38717022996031,1.73678621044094,2.08635690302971,2.43482272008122,
2.78323181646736,3.09261553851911,3.40196944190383,3.71141458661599,4.02084988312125,
4.58891497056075,5.15713879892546,5.76275031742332,6.36807269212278,6.57340116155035,
6.77833051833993),.UNSPECIFIED.);
#1099=EDGE_CURVE('E58',#1045,#32,#1098,.T.);
#1100=ORIENTED_EDGE('',*,*,#1099,.T.);
#1101=ORIENTED_EDGE('',*,*,#33,.F.);
#1102=ORIENTED_EDGE('',*,*,#541,.T.);
#1103=ORIENTED_EDGE('',*,*,#507,.T.);
#1104=ORIENTED_EDGE('',*,*,#426,.T.);
#1105=ORIENTED_EDGE('',*,*,#475,.T.);
#1106=ORIENTED_EDGE('',*,*,#705,.T.);
#1107=EDGE_LOOP('',(#1059,#1100,#1101,#1102,#1103,#1104,#1105,#1106));
#1108=FACE_BOUND('',#1107,.T.);
#1109=ORIENTED_EDGE('',*,*,#204,.T.);
#1110=EDGE_LOOP('',(#1109));
#1111=FACE_BOUND('',#1110,.T.);
#1112=ADVANCED_FACE('F292',(#1108,#1111),#1058,.F.);
#1113=CARTESIAN_POINT('',(13.6906,0.,2.6797));
#1114=DIRECTION('',(0.,0.,-1.));
#1115=DIRECTION('',(-1.,0.,0.));
#1116=AXIS2_PLACEMENT_3D('',#1113,#1114,#1115);
#1117=PLANE('',#1116);
#1118=ORIENTED_EDGE('',*,*,#782,.F.);
#1119=DIRECTION('',(1.,0.,0.));
#1120=VECTOR('',#1119,1.);
#1121=CARTESIAN_POINT('',(39.44747,2.92748774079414,2.6797));
#1122=LINE('',#1121,#1120);
#1123=CARTESIAN_POINT('',(13.996296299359,2.92748774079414,2.6797));
#1124=VERTEX_POINT('',#1123);
#1125=EDGE_CURVE('E688',#772,#1124,#1122,.T.);
#1126=ORIENTED_EDGE('',*,*,#1125,.T.);
#1127=CARTESIAN_POINT('',(8.128,0.,2.6797));
#1128=DIRECTION('',(0.,0.,1.));
#1129=DIRECTION('',(1.,0.,0.));
#1130=AXIS2_PLACEMENT_3D('',#1127,#1128,#1129);
#1131=CIRCLE('',#1130,6.55797879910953);
#1132=CARTESIAN_POINT('',(13.996296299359,-2.92748774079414,2.6797));
#1133=VERTEX_POINT('',#1132);
#1134=EDGE_CURVE('E201',#1124,#1133,#1131,.T.);
#1135=ORIENTED_EDGE('',*,*,#1134,.T.);
#1136=DIRECTION('',(1.,0.,0.));
#1137=VECTOR('',#1136,1.);
#1138=CARTESIAN_POINT('',(39.44747,-2.92748774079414,2.6797));
#1139=LINE('',#1138,#1137);
#1140=EDGE_CURVE('E50',#1133,#781,#1139,.F.);
#1141=ORIENTED_EDGE('',*,*,#1140,.T.);
#1142=EDGE_LOOP('',(#1118,#1126,#1135,#1141));
#1143=FACE_BOUND('',#1142,.T.);
#1144=ADVANCED_FACE('F299',(#1143),#1117,.F.);
#1145=CARTESIAN_POINT('',(8.128,0.,12.7));
#1146=DIRECTION('',(0.,0.,1.));
#1147=DIRECTION('',(1.,0.,0.));
#1148=AXIS2_PLACEMENT_3D('',#1145,#1146,#1147);
#1149=CONICAL_SURFACE('',#1148,6.858,0.0299323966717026);
#1150=ORIENTED_EDGE('',*,*,#1134,.F.);
#1151=CARTESIAN_POINT('',(13.9961982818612,2.92767079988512,2.6795));
#1152=CARTESIAN_POINT('',(14.0353597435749,2.85454905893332,2.7593870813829));
#1153=CARTESIAN_POINT('',(14.0743107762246,2.7781013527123,2.83635574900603));
#1154=CARTESIAN_POINT('',(14.1509987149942,2.61877561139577,2.98409314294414));
#1155=CARTESIAN_POINT('',(14.1887348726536,2.53589371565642,3.05485809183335));
#1156=CARTESIAN_POINT('',(14.2624104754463,2.36340150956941,3.19020500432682));
#1157=CARTESIAN_POINT('',(14.2983352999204,2.27374769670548,3.25473961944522));
#1158=CARTESIAN_POINT('',(14.36728774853,2.08859219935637,3.37654207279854));
#1159=CARTESIAN_POINT('',(14.4003158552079,1.99309149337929,3.43381112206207));
#1160=CARTESIAN_POINT('',(14.4628419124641,1.79621765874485,3.54078869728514));
#1161=CARTESIAN_POINT('',(14.4923230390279,1.69481968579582,3.59046147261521));
#1162=CARTESIAN_POINT('',(14.5468203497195,1.48714488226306,3.68133388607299));
#1163=CARTESIAN_POINT('',(14.5718371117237,1.38086868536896,3.7225346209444));
#1164=CARTESIAN_POINT('',(14.6166486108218,1.16451545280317,3.7957714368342));
#1165=CARTESIAN_POINT('',(14.6364596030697,1.05445149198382,3.82783607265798));
#1166=CARTESIAN_POINT('',(14.6703758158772,0.831131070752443,3.88244827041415));
#1167=CARTESIAN_POINT('',(14.6844819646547,0.717875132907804,3.90499738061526));
#1168=CARTESIAN_POINT('',(14.705315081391,0.502058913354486,3.93820567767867));
#1169=CARTESIAN_POINT('',(14.7126916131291,0.399721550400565,3.94991374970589));
#1170=CARTESIAN_POINT('',(14.7224150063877,0.194213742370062,3.96533401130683));
#1171=CARTESIAN_POINT('',(14.7247623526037,0.0910433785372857,3.96904697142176));
#1172=CARTESIAN_POINT('',(14.7243636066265,-0.115298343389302,3.96841596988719));
#1173=CARTESIAN_POINT('',(14.7216160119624,-0.218469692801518,3.96406963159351));
#1174=CARTESIAN_POINT('',(14.7111063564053,-0.423877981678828,3.94739645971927));
#1175=CARTESIAN_POINT('',(14.7033444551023,-0.52611495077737,3.93506988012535));
#1176=CARTESIAN_POINT('',(14.6744558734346,-0.813692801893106,3.88900261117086));
#1177=CARTESIAN_POINT('',(14.6475810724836,-0.997072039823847,3.84597487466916));
#1178=CARTESIAN_POINT('',(14.5796655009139,-1.35341922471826,3.73552214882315));
#1179=CARTESIAN_POINT('',(14.5386207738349,-1.52638424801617,3.66809034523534));
#1180=CARTESIAN_POINT('',(14.4422881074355,-1.86972678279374,3.5062028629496));
#1181=CARTESIAN_POINT('',(14.3862406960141,-2.03918522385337,3.41026101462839));
#1182=CARTESIAN_POINT('',(14.2655350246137,-2.36015651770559,3.19653083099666));
#1183=CARTESIAN_POINT('',(14.2008808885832,-2.51167789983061,3.07875294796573));
#1184=CARTESIAN_POINT('',(14.1114970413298,-2.70138241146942,2.90821063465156));
#1185=CARTESIAN_POINT('',(14.0886166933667,-2.74829708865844,2.86391334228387));
#1186=CARTESIAN_POINT('',(14.0425824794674,-2.83974577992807,2.77325644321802));
#1187=CARTESIAN_POINT('',(14.0194292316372,-2.88428424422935,2.72690101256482));
#1188=CARTESIAN_POINT('',(13.9961982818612,-2.92767079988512,2.6795));
#1189=B_SPLINE_CURVE_WITH_KNOTS('',3,(#1151,#1152,#1153,#1154,#1155,#1156,#1157,#1158,#1159,
#1160,#1161,#1162,#1163,#1164,#1165,#1166,#1167,#1168,#1169,#1170,#1171,#1172,#1173,#1174,#1175,
#1176,#1177,#1178,#1179,#1180,#1181,#1182,#1183,#1184,#1185,#1186,#1187,#1188),.UNSPECIFIED.,
.F.,.F.,(4,2,2,2,2,2,2,2,2,2,2,2,2,2,2,2,2,2,4),(0.,0.345426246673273,0.691061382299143,
1.03914485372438,1.38717022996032,1.73678621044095,2.08635690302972,2.43482272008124,
2.78323181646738,3.09261553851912,3.40196944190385,3.71141458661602,4.02084988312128,
4.58891497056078,5.15713879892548,5.76275031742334,6.3680726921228,6.57340116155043,
6.77833051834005),.UNSPECIFIED.);
#1190=EDGE_CURVE('E237',#1124,#1133,#1189,.T.);
#1191=ORIENTED_EDGE('',*,*,#1190,.T.);
#1192=EDGE_LOOP('',(#1150,#1191));
#1193=FACE_BOUND('',#1192,.T.);
#1194=ORIENTED_EDGE('',*,*,#193,.T.);
#1195=EDGE_LOOP('',(#1194));
#1196=FACE_BOUND('',#1195,.T.);
#1197=ADVANCED_FACE('F639',(#1193,#1196),#1149,.F.);
#1198=CARTESIAN_POINT('',(12.26947,3.45439999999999,0.));
#1199=DIRECTION('',(-1.,0.,0.));
#1200=DIRECTION('',(0.,0.,1.));
#1201=AXIS2_PLACEMENT_3D('',#1198,#1199,#1200);
#1202=PLANE('',#1201);
#1203=CARTESIAN_POINT('',(12.26947,0.,0.));
#1204=DIRECTION('',(1.,0.,0.));
#1205=DIRECTION('',(0.,0.,-1.));
#1206=AXIS2_PLACEMENT_3D('',#1203,#1204,#1205);
#1207=CIRCLE('',#1206,3.96874999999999);
#1208=EDGE_CURVE('E182',#749,#757,#1207,.T.);
#1209=ORIENTED_EDGE('',*,*,#1208,.T.);
#1210=ORIENTED_EDGE('',*,*,#758,.F.);
#1211=EDGE_LOOP('',(#1209,#1210));
#1212=FACE_BOUND('',#1211,.T.);
#1213=ADVANCED_FACE('F181',(#1212),#1202,.F.);
#1214=EDGE_CURVE('E190',#796,#804,#1207,.T.);
#1215=ORIENTED_EDGE('',*,*,#1214,.T.);
#1216=ORIENTED_EDGE('',*,*,#805,.F.);
#1217=EDGE_LOOP('',(#1215,#1216));
#1218=FACE_BOUND('',#1217,.T.);
#1219=ADVANCED_FACE('F218',(#1218),#1202,.F.);
#1220=CARTESIAN_POINT('',(39.44747,0.,0.));
#1221=DIRECTION('',(1.,0.,0.));
#1222=DIRECTION('',(0.,0.,-1.));
#1223=AXIS2_PLACEMENT_3D('',#1220,#1221,#1222);
#1224=CYLINDRICAL_SURFACE('',#1223,3.96875);
#1225=ORIENTED_EDGE('',*,*,#41,.F.);
#1226=ORIENTED_EDGE('',*,*,#1099,.F.);
#1227=ORIENTED_EDGE('',*,*,#1046,.F.);
#1228=ORIENTED_EDGE('',*,*,#1025,.F.);
#1229=EDGE_LOOP('',(#1225,#1226,#1227,#1228));
#1230=FACE_BOUND('',#1229,.T.);
#1231=ORIENTED_EDGE('',*,*,#850,.F.);
#1232=ORIENTED_EDGE('',*,*,#900,.F.);
#1233=ORIENTED_EDGE('',*,*,#835,.F.);
#1234=ORIENTED_EDGE('',*,*,#818,.F.);
#1235=ORIENTED_EDGE('',*,*,#1214,.F.);
#1236=ORIENTED_EDGE('',*,*,#797,.F.);
#1237=ORIENTED_EDGE('',*,*,#1140,.F.);
#1238=ORIENTED_EDGE('',*,*,#1190,.F.);
#1239=ORIENTED_EDGE('',*,*,#1125,.F.);
#1240=ORIENTED_EDGE('',*,*,#773,.F.);
#1241=ORIENTED_EDGE('',*,*,#1208,.F.);
#1242=ORIENTED_EDGE('',*,*,#750,.F.);
#1243=EDGE_LOOP('',(#1231,#1232,#1233,#1234,#1235,#1236,#1237,#1238,#1239,#1240,#1241,#1242));
#1244=FACE_BOUND('',#1243,.T.);
#1245=ADVANCED_FACE('F186',(#1230,#1244),#1224,.F.);
#1246=CLOSED_SHELL('',(#60,#85,#113,#180,#233,#257,#281,#316,#340,#357,#371,#383,#440,#518,#710,
#720,#822,#854,#907,#927,#1038,#1053,#1112,#1144,#1197,#1213,#1219,#1245));
#1247=MANIFOLD_SOLID_BREP('B2',#1246);
#1248=ADVANCED_BREP_SHAPE_REPRESENTATION('',(#18,#1247),#14);
#1249=SHAPE_DEFINITION_REPRESENTATION(#9,#1248);
ENDSEC;
END-ISO-10303-21;
